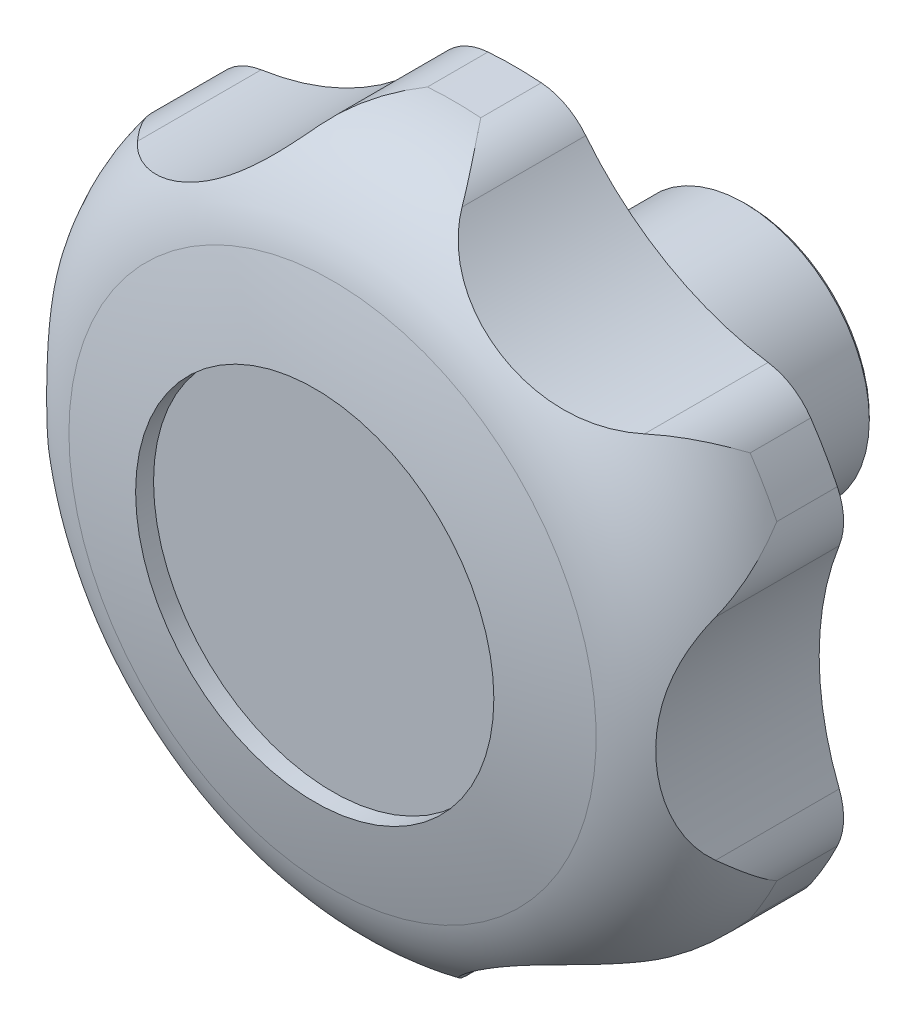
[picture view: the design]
ISO-10303-21;
HEADER;
FILE_DESCRIPTION(('STEP AP214'),'2;1');
FILE_NAME('part.step','',(''),(''),'','','');
FILE_SCHEMA(('AUTOMOTIVE_DESIGN { 1 0 10303 214 1 1 1 1 }'));
ENDSEC;
DATA;
#1=APPLICATION_CONTEXT('core data for automotive mechanical design processes');
#2=APPLICATION_PROTOCOL_DEFINITION('international standard','automotive_design',2000,#1);
#3=PRODUCT_CONTEXT('',#1,'mechanical');
#4=PRODUCT('Part','Part','',(#3));
#5=PRODUCT_RELATED_PRODUCT_CATEGORY('part','',(#4));
#6=PRODUCT_DEFINITION_FORMATION('','',#4);
#7=PRODUCT_DEFINITION_CONTEXT('part definition',#1,'design');
#8=PRODUCT_DEFINITION('design','',#6,#7);
#9=PRODUCT_DEFINITION_SHAPE('','',#8);
#10=(LENGTH_UNIT() NAMED_UNIT(*) SI_UNIT(.MILLI.,.METRE.));
#11=(NAMED_UNIT(*) PLANE_ANGLE_UNIT() SI_UNIT($,.RADIAN.));
#12=(NAMED_UNIT(*) SI_UNIT($,.STERADIAN.) SOLID_ANGLE_UNIT());
#13=UNCERTAINTY_MEASURE_WITH_UNIT(LENGTH_MEASURE(1.E-05),#10,'distance_accuracy_value','');
#14=(GEOMETRIC_REPRESENTATION_CONTEXT(3) GLOBAL_UNCERTAINTY_ASSIGNED_CONTEXT((#13)) GLOBAL_UNIT_ASSIGNED_CONTEXT((#10,
#11,#12)) REPRESENTATION_CONTEXT('',''));
#15=CARTESIAN_POINT('',(0.,0.,0.));
#16=DIRECTION('',(0.,0.,1.));
#17=DIRECTION('',(1.,0.,0.));
#18=AXIS2_PLACEMENT_3D('',#15,#16,#17);
#19=CARTESIAN_POINT('',(0.,0.,35.0080113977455));
#20=DIRECTION('',(0.,0.,1.));
#21=DIRECTION('',(-1.,0.,0.));
#22=AXIS2_PLACEMENT_3D('',#19,#20,#21);
#23=CYLINDRICAL_SURFACE('',#22,20.);
#24=CARTESIAN_POINT('',(0.,0.,13.));
#25=DIRECTION('',(0.,0.,1.));
#26=DIRECTION('',(-1.,0.,0.));
#27=AXIS2_PLACEMENT_3D('',#24,#25,#26);
#28=CIRCLE('',#27,20.);
#29=CARTESIAN_POINT('',(1.4880574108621,19.9445653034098,12.9999999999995));
#30=VERTEX_POINT('',#29);
#31=CARTESIAN_POINT('',(-1.48805741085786,19.94456530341,12.9999999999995));
#32=VERTEX_POINT('',#31);
#33=EDGE_CURVE('E459',#30,#32,#28,.T.);
#34=ORIENTED_EDGE('',*,*,#33,.T.);
#35=DIRECTION('',(0.,0.,1.));
#36=VECTOR('',#35,1.);
#37=CARTESIAN_POINT('',(-1.48805741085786,19.94456530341,-4.9960036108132E-13));
#38=LINE('',#37,#36);
#39=CARTESIAN_POINT('',(-1.48805741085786,19.94456530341,16.38093031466));
#40=VERTEX_POINT('',#39);
#41=EDGE_CURVE('E182',#32,#40,#38,.T.);
#42=ORIENTED_EDGE('',*,*,#41,.T.);
#43=CARTESIAN_POINT('',(0.,0.,16.38093031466));
#44=DIRECTION('',(0.,0.,1.));
#45=DIRECTION('',(-1.,0.,0.));
#46=AXIS2_PLACEMENT_3D('',#43,#44,#45);
#47=CIRCLE('',#46,20.);
#48=CARTESIAN_POINT('',(1.4880574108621,19.9445653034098,16.38093031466));
#49=VERTEX_POINT('',#48);
#50=EDGE_CURVE('E198',#49,#40,#47,.T.);
#51=ORIENTED_EDGE('',*,*,#50,.F.);
#52=DIRECTION('',(0.,0.,1.));
#53=VECTOR('',#52,1.);
#54=CARTESIAN_POINT('',(1.4880574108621,19.9445653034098,-4.9960036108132E-13));
#55=LINE('',#54,#53);
#56=EDGE_CURVE('E578',#30,#49,#55,.T.);
#57=ORIENTED_EDGE('',*,*,#56,.F.);
#58=EDGE_LOOP('',(#34,#42,#51,#57));
#59=FACE_BOUND('',#58,.T.);
#60=ADVANCED_FACE('F14',(#59),#23,.T.);
#61=CARTESIAN_POINT('',(18.0165289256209,8.68358713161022,12.9999999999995));
#62=VERTEX_POINT('',#61);
#63=CARTESIAN_POINT('',(16.5284715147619,11.2609781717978,13.));
#64=VERTEX_POINT('',#63);
#65=EDGE_CURVE('E463',#62,#64,#28,.T.);
#66=ORIENTED_EDGE('',*,*,#65,.T.);
#67=DIRECTION('',(0.,0.,1.));
#68=VECTOR('',#67,1.);
#69=CARTESIAN_POINT('',(16.5284715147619,11.2609781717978,-4.9960036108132E-13));
#70=LINE('',#69,#68);
#71=CARTESIAN_POINT('',(16.5284715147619,11.2609781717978,16.38093031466));
#72=VERTEX_POINT('',#71);
#73=EDGE_CURVE('E491',#64,#72,#70,.T.);
#74=ORIENTED_EDGE('',*,*,#73,.T.);
#75=CARTESIAN_POINT('',(18.0165289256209,8.68358713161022,16.38093031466));
#76=VERTEX_POINT('',#75);
#77=EDGE_CURVE('E553',#76,#72,#47,.T.);
#78=ORIENTED_EDGE('',*,*,#77,.F.);
#79=DIRECTION('',(0.,0.,1.));
#80=VECTOR('',#79,1.);
#81=CARTESIAN_POINT('',(18.0165289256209,8.68358713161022,-4.9960036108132E-13));
#82=LINE('',#81,#80);
#83=EDGE_CURVE('E493',#62,#76,#82,.T.);
#84=ORIENTED_EDGE('',*,*,#83,.F.);
#85=EDGE_LOOP('',(#66,#74,#78,#84));
#86=FACE_BOUND('',#85,.T.);
#87=ADVANCED_FACE('F429',(#86),#23,.T.);
#88=CARTESIAN_POINT('',(16.5284715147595,-11.260978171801,12.9999999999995));
#89=VERTEX_POINT('',#88);
#90=CARTESIAN_POINT('',(18.0165289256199,-8.68358713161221,13.));
#91=VERTEX_POINT('',#90);
#92=EDGE_CURVE('E476',#89,#91,#28,.T.);
#93=ORIENTED_EDGE('',*,*,#92,.T.);
#94=DIRECTION('',(0.,0.,1.));
#95=VECTOR('',#94,1.);
#96=CARTESIAN_POINT('',(18.0165289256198,-8.68358713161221,-4.9960036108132E-13));
#97=LINE('',#96,#95);
#98=CARTESIAN_POINT('',(18.0165289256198,-8.68358713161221,16.38093031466));
#99=VERTEX_POINT('',#98);
#100=EDGE_CURVE('E569',#91,#99,#97,.T.);
#101=ORIENTED_EDGE('',*,*,#100,.T.);
#102=CARTESIAN_POINT('',(16.5284715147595,-11.260978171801,16.38093031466));
#103=VERTEX_POINT('',#102);
#104=EDGE_CURVE('E548',#103,#99,#47,.T.);
#105=ORIENTED_EDGE('',*,*,#104,.F.);
#106=DIRECTION('',(0.,0.,1.));
#107=VECTOR('',#106,1.);
#108=CARTESIAN_POINT('',(16.5284715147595,-11.260978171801,-4.9960036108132E-13));
#109=LINE('',#108,#107);
#110=EDGE_CURVE('E612',#89,#103,#109,.T.);
#111=ORIENTED_EDGE('',*,*,#110,.F.);
#112=EDGE_LOOP('',(#93,#101,#105,#111));
#113=FACE_BOUND('',#112,.T.);
#114=ADVANCED_FACE('F437',(#113),#23,.T.);
#115=CARTESIAN_POINT('',(-1.48805741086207,-19.94456530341,12.9999999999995));
#116=VERTEX_POINT('',#115);
#117=CARTESIAN_POINT('',(1.48805741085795,-19.94456530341,13.));
#118=VERTEX_POINT('',#117);
#119=EDGE_CURVE('E470',#116,#118,#28,.T.);
#120=ORIENTED_EDGE('',*,*,#119,.T.);
#121=DIRECTION('',(0.,0.,1.));
#122=VECTOR('',#121,1.);
#123=CARTESIAN_POINT('',(1.48805741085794,-19.94456530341,-4.9960036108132E-13));
#124=LINE('',#123,#122);
#125=CARTESIAN_POINT('',(1.48805741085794,-19.94456530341,16.38093031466));
#126=VERTEX_POINT('',#125);
#127=EDGE_CURVE('E604',#118,#126,#124,.T.);
#128=ORIENTED_EDGE('',*,*,#127,.T.);
#129=CARTESIAN_POINT('',(-1.48805741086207,-19.94456530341,16.38093031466));
#130=VERTEX_POINT('',#129);
#131=EDGE_CURVE('E543',#130,#126,#47,.T.);
#132=ORIENTED_EDGE('',*,*,#131,.F.);
#133=DIRECTION('',(0.,0.,1.));
#134=VECTOR('',#133,1.);
#135=CARTESIAN_POINT('',(-1.48805741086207,-19.94456530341,-4.9960036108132E-13));
#136=LINE('',#135,#134);
#137=EDGE_CURVE('E602',#116,#130,#136,.T.);
#138=ORIENTED_EDGE('',*,*,#137,.F.);
#139=EDGE_LOOP('',(#120,#128,#132,#138));
#140=FACE_BOUND('',#139,.T.);
#141=ADVANCED_FACE('F449',(#140),#23,.T.);
#142=CARTESIAN_POINT('',(-18.0165289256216,-8.68358713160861,12.9999999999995));
#143=VERTEX_POINT('',#142);
#144=CARTESIAN_POINT('',(-16.528471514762,-11.2609781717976,13.));
#145=VERTEX_POINT('',#144);
#146=EDGE_CURVE('E462',#143,#145,#28,.T.);
#147=ORIENTED_EDGE('',*,*,#146,.T.);
#148=DIRECTION('',(0.,0.,1.));
#149=VECTOR('',#148,1.);
#150=CARTESIAN_POINT('',(-16.5284715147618,-11.2609781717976,-4.9960036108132E-13));
#151=LINE('',#150,#149);
#152=CARTESIAN_POINT('',(-16.5284715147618,-11.2609781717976,16.38093031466));
#153=VERTEX_POINT('',#152);
#154=EDGE_CURVE('E594',#145,#153,#151,.T.);
#155=ORIENTED_EDGE('',*,*,#154,.T.);
#156=CARTESIAN_POINT('',(-18.0165289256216,-8.68358713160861,16.38093031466));
#157=VERTEX_POINT('',#156);
#158=EDGE_CURVE('E474',#157,#153,#47,.T.);
#159=ORIENTED_EDGE('',*,*,#158,.F.);
#160=DIRECTION('',(0.,0.,1.));
#161=VECTOR('',#160,1.);
#162=CARTESIAN_POINT('',(-18.0165289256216,-8.68358713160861,-4.9960036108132E-13));
#163=LINE('',#162,#161);
#164=EDGE_CURVE('E592',#143,#157,#163,.T.);
#165=ORIENTED_EDGE('',*,*,#164,.F.);
#166=EDGE_LOOP('',(#147,#155,#159,#165));
#167=FACE_BOUND('',#166,.T.);
#168=ADVANCED_FACE('F441',(#167),#23,.T.);
#169=CARTESIAN_POINT('',(-16.5284715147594,11.260978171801,12.9999999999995));
#170=VERTEX_POINT('',#169);
#171=CARTESIAN_POINT('',(-18.0165289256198,8.68358713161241,13.));
#172=VERTEX_POINT('',#171);
#173=EDGE_CURVE('E454',#170,#172,#28,.T.);
#174=ORIENTED_EDGE('',*,*,#173,.T.);
#175=DIRECTION('',(0.,0.,1.));
#176=VECTOR('',#175,1.);
#177=CARTESIAN_POINT('',(-18.0165289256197,8.68358713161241,-4.9960036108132E-13));
#178=LINE('',#177,#176);
#179=CARTESIAN_POINT('',(-18.0165289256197,8.68358713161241,16.38093031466));
#180=VERTEX_POINT('',#179);
#181=EDGE_CURVE('E37',#172,#180,#178,.T.);
#182=ORIENTED_EDGE('',*,*,#181,.T.);
#183=CARTESIAN_POINT('',(-16.5284715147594,11.260978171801,16.38093031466));
#184=VERTEX_POINT('',#183);
#185=EDGE_CURVE('E469',#184,#180,#47,.T.);
#186=ORIENTED_EDGE('',*,*,#185,.F.);
#187=DIRECTION('',(0.,0.,1.));
#188=VECTOR('',#187,1.);
#189=CARTESIAN_POINT('',(-16.5284715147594,11.260978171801,-4.9960036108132E-13));
#190=LINE('',#189,#188);
#191=EDGE_CURVE('E457',#170,#184,#190,.T.);
#192=ORIENTED_EDGE('',*,*,#191,.F.);
#193=EDGE_LOOP('',(#174,#182,#186,#192));
#194=FACE_BOUND('',#193,.T.);
#195=ADVANCED_FACE('F431',(#194),#23,.T.);
#196=CARTESIAN_POINT('',(0.,0.,-35.0000000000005));
#197=DIRECTION('',(-1.,0.,0.));
#198=DIRECTION('',(0.,0.,-1.));
#199=AXIS2_PLACEMENT_3D('',#196,#197,#198);
#200=SPHERICAL_SURFACE('',#199,60.);
#201=CARTESIAN_POINT('',(0.,0.,-35.0000000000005));
#202=DIRECTION('',(0.,0.,1.));
#203=DIRECTION('',(-1.,0.,0.));
#204=AXIS2_PLACEMENT_3D('',#201,#202,#203);
#205=SPHERICAL_SURFACE('',#204,60.);
#206=CARTESIAN_POINT('',(0.,0.,23.167090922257));
#207=DIRECTION('',(0.,0.,1.));
#208=DIRECTION('',(-1.,0.,0.));
#209=AXIS2_PLACEMENT_3D('',#206,#207,#208);
#210=CIRCLE('',#209,14.7169811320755);
#211=CARTESIAN_POINT('',(-14.7169811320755,0.,23.167090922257));
#212=VERTEX_POINT('',#211);
#213=EDGE_CURVE('E540',#212,#212,#210,.T.);
#214=ORIENTED_EDGE('',*,*,#213,.T.);
#215=EDGE_LOOP('',(#214));
#216=FACE_BOUND('',#215,.T.);
#217=CARTESIAN_POINT('',(0.,0.,24.160797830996));
#218=DIRECTION('',(0.,0.,1.));
#219=DIRECTION('',(-1.,0.,0.));
#220=AXIS2_PLACEMENT_3D('',#217,#218,#219);
#221=CIRCLE('',#220,10.);
#222=CARTESIAN_POINT('',(-10.,0.,24.160797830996));
#223=VERTEX_POINT('',#222);
#224=EDGE_CURVE('E199',#223,#223,#221,.T.);
#225=ORIENTED_EDGE('',*,*,#224,.F.);
#226=EDGE_LOOP('',(#225));
#227=FACE_BOUND('',#226,.T.);
#228=ADVANCED_FACE('F16',(#216,#227),#205,.T.);
#229=CARTESIAN_POINT('',(0.,0.,16.38093031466));
#230=DIRECTION('',(0.,0.,1.));
#231=DIRECTION('',(-1.,0.,0.));
#232=AXIS2_PLACEMENT_3D('',#229,#230,#231);
#233=TOROIDAL_SURFACE('',#232,13.,7.);
#234=CARTESIAN_POINT('',(1.48805741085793,19.94456530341,16.38093031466));
#235=CARTESIAN_POINT('',(1.49147422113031,19.9443103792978,16.3853314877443));
#236=CARTESIAN_POINT('',(1.49489072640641,19.9440504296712,16.389732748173));
#237=CARTESIAN_POINT('',(1.81379375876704,19.9193149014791,16.8006005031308));
#238=CARTESIAN_POINT('',(2.12658065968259,19.8519874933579,17.2077752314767));
#239=CARTESIAN_POINT('',(2.72890668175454,19.6321878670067,18.0173039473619));
#240=CARTESIAN_POINT('',(3.01841511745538,19.4796053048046,18.4196509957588));
#241=CARTESIAN_POINT('',(3.4111136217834,19.1940432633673,19.0006622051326));
#242=CARTESIAN_POINT('',(3.53138560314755,19.0939385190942,19.1842811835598));
#243=CARTESIAN_POINT('',(3.759784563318,18.875652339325,19.5475677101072));
#244=CARTESIAN_POINT('',(3.86793749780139,18.7575108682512,19.7272430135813));
#245=CARTESIAN_POINT('',(3.96899762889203,18.6302715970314,19.9047576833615));
#246=B_SPLINE_CURVE_WITH_KNOTS('',3,(#234,#235,#236,#237,#238,#239,#240,#241,#242,#243,#244,
#245),.UNSPECIFIED.,.F.,.F.,(4,2,2,2,2,4),(0.,0.0167332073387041,1.56205380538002,
3.1093791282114,3.83223807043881,4.55351799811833),.UNSPECIFIED.);
#247=CARTESIAN_POINT('',(3.96883886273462,18.6304715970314,19.9044786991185));
#248=VERTEX_POINT('',#247);
#249=EDGE_CURVE('E200',#49,#248,#246,.T.);
#250=ORIENTED_EDGE('',*,*,#249,.F.);
#251=ORIENTED_EDGE('',*,*,#50,.T.);
#252=CARTESIAN_POINT('',(-3.96899762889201,18.6302715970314,19.9047576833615));
#253=CARTESIAN_POINT('',(-3.87488306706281,18.7487894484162,19.7394301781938));
#254=CARTESIAN_POINT('',(-3.77455997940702,18.8594451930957,19.5721519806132));
#255=CARTESIAN_POINT('',(-3.56354943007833,19.0648747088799,19.234567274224));
#256=CARTESIAN_POINT('',(-3.45286825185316,19.1596580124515,19.0642626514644));
#257=CARTESIAN_POINT('',(-3.22337066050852,19.3331052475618,18.7217368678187));
#258=CARTESIAN_POINT('',(-3.10457584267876,19.4118099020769,18.5495217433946));
#259=CARTESIAN_POINT('',(-2.86030415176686,19.5533565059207,18.2033602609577));
#260=CARTESIAN_POINT('',(-2.73482744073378,19.6161988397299,18.0294139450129));
#261=CARTESIAN_POINT('',(-2.42924956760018,19.7472078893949,17.6128190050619));
#262=CARTESIAN_POINT('',(-2.24677265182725,19.8080525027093,17.3695899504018));
#263=CARTESIAN_POINT('',(-1.87597960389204,19.8989790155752,16.8822329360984));
#264=CARTESIAN_POINT('',(-1.68767071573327,19.9290976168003,16.638106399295));
#265=CARTESIAN_POINT('',(-1.49489075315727,19.9440504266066,16.3897327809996));
#266=CARTESIAN_POINT('',(-1.49147424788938,19.9443103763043,16.385331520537));
#267=CARTESIAN_POINT('',(-1.4880574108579,19.94456530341,16.38093031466));
#268=B_SPLINE_CURVE_WITH_KNOTS('',3,(#252,#253,#254,#255,#256,#257,#258,#259,#260,#261,#262,
#263,#264,#265,#266,#267),.UNSPECIFIED.,.F.,.F.,(4,2,2,2,2,2,2,4),(0.,0.672016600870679,
1.34362815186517,2.01351700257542,2.68338961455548,3.61205098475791,4.53960178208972,
4.55633498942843),.UNSPECIFIED.);
#269=CARTESIAN_POINT('',(-3.96883886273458,18.6304715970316,19.9044786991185));
#270=VERTEX_POINT('',#269);
#271=EDGE_CURVE('E186',#270,#40,#268,.T.);
#272=ORIENTED_EDGE('',*,*,#271,.F.);
#273=CARTESIAN_POINT('',(-3.96868008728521,18.6306715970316,19.9041996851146));
#274=CARTESIAN_POINT('',(-4.04437009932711,18.5352984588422,20.0373324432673));
#275=CARTESIAN_POINT('',(-4.12526413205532,18.4356613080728,20.1643450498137));
#276=CARTESIAN_POINT('',(-4.29682494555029,18.2299121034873,20.4055808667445));
#277=CARTESIAN_POINT('',(-4.38747947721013,18.1238082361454,20.5198197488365));
#278=CARTESIAN_POINT('',(-4.57713747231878,17.9080462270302,20.734184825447));
#279=CARTESIAN_POINT('',(-4.67604562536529,17.7984357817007,20.8344439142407));
#280=CARTESIAN_POINT('',(-4.88238077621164,17.5763891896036,21.0223145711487));
#281=CARTESIAN_POINT('',(-4.98981004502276,17.4639522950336,21.1099227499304));
#282=CARTESIAN_POINT('',(-5.21195811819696,17.2384215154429,21.2724206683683));
#283=CARTESIAN_POINT('',(-5.32664134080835,17.1253329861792,21.3473667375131));
#284=CARTESIAN_POINT('',(-5.5630216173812,16.8994018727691,21.4855727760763));
#285=CARTESIAN_POINT('',(-5.68471815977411,16.7865592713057,21.5488335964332));
#286=CARTESIAN_POINT('',(-5.93480326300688,16.5619776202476,21.6645190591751));
#287=CARTESIAN_POINT('',(-6.06320974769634,16.4502425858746,21.7169126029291));
#288=CARTESIAN_POINT('',(-6.32576627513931,16.2291643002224,21.8113760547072));
#289=CARTESIAN_POINT('',(-6.45991755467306,16.1198215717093,21.8534437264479));
#290=CARTESIAN_POINT('',(-6.79339160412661,15.8570291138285,21.9443164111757));
#291=CARTESIAN_POINT('',(-6.99547686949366,15.7052831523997,21.9879752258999));
#292=CARTESIAN_POINT('',(-7.40871955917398,15.410195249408,22.0571569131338));
#293=CARTESIAN_POINT('',(-7.61988028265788,15.2668564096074,22.0826731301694));
#294=CARTESIAN_POINT('',(-8.05020035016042,14.9896326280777,22.1167506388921));
#295=CARTESIAN_POINT('',(-8.26937403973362,14.8557660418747,22.1252798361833));
#296=CARTESIAN_POINT('',(-8.71390124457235,14.59876043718,22.1256982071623));
#297=CARTESIAN_POINT('',(-8.93925403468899,14.4756201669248,22.1175893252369));
#298=CARTESIAN_POINT('',(-9.3969107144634,14.2396244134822,22.0841784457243));
#299=CARTESIAN_POINT('',(-9.62926146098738,14.1268834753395,22.0587061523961));
#300=CARTESIAN_POINT('',(-10.0969036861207,13.9136966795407,21.9891901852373));
#301=CARTESIAN_POINT('',(-10.3321956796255,13.8132530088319,21.9451432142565));
#302=CARTESIAN_POINT('',(-10.8026152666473,13.6254517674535,21.8367845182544));
#303=CARTESIAN_POINT('',(-11.0377415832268,13.5380595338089,21.7725279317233));
#304=CARTESIAN_POINT('',(-11.5052304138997,13.37642671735,21.6215210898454));
#305=CARTESIAN_POINT('',(-11.7375946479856,13.3021775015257,21.5347856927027));
#306=CARTESIAN_POINT('',(-12.1176745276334,13.1898767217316,21.3703811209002));
#307=CARTESIAN_POINT('',(-12.2673166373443,13.1480997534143,21.2996511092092));
#308=CARTESIAN_POINT('',(-12.5622706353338,13.0702110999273,21.1469698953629));
#309=CARTESIAN_POINT('',(-12.707583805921,13.0340977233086,21.0650220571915));
#310=CARTESIAN_POINT('',(-12.9920623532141,12.967442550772,20.8897703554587));
#311=CARTESIAN_POINT('',(-13.1312411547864,12.9368880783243,20.7964931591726));
#312=CARTESIAN_POINT('',(-13.4021505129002,12.880989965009,20.5983767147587));
#313=CARTESIAN_POINT('',(-13.5338850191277,12.8556435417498,20.4935436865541));
#314=CARTESIAN_POINT('',(-13.7470664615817,12.817207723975,20.3083350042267));
#315=CARTESIAN_POINT('',(-13.8309740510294,12.8028082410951,20.2310445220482));
#316=CARTESIAN_POINT('',(-13.9941817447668,12.7760624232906,20.0714083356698));
#317=CARTESIAN_POINT('',(-14.0734817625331,12.7637161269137,19.9890625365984));
#318=CARTESIAN_POINT('',(-14.1502422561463,12.7523213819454,19.9042577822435));
#319=B_SPLINE_CURVE_WITH_KNOTS('',3,(#273,#274,#275,#276,#277,#278,#279,#280,#281,#282,#283,
#284,#285,#286,#287,#288,#289,#290,#291,#292,#293,#294,#295,#296,#297,#298,#299,#300,#301,#302,
#303,#304,#305,#306,#307,#308,#309,#310,#311,#312,#313,#314,#315,#316,#317,#318),.UNSPECIFIED.,
.F.,.F.,(4,2,2,2,2,2,2,2,2,2,2,2,2,2,2,2,2,2,2,2,2,2,4),(0.,0.540904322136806,1.08113756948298,
1.61582234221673,2.15065009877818,2.68303208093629,3.21537527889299,3.7492214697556,
4.28318317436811,5.05149336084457,5.82008525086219,6.5901279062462,7.36008057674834,
8.13769549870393,8.91544851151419,9.69109770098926,10.4662354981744,10.9779030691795,
11.4894175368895,11.9997505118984,12.5098101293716,12.8545587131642,13.1993137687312),.UNSPECIFIED.);
#320=CARTESIAN_POINT('',(-14.1500422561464,12.7523510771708,19.9044786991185));
#321=VERTEX_POINT('',#320);
#322=EDGE_CURVE('E174',#270,#321,#319,.T.);
#323=ORIENTED_EDGE('',*,*,#322,.T.);
#324=CARTESIAN_POINT('',(-16.5284715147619,11.2609781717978,16.38093031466));
#325=CARTESIAN_POINT('',(-16.526542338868,11.2638097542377,16.3853314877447));
#326=CARTESIAN_POINT('',(-16.5246089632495,11.2666385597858,16.3897327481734));
#327=CARTESIAN_POINT('',(-16.3437358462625,11.5304489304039,16.8006005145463));
#328=CARTESIAN_POINT('',(-16.1290351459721,11.7676666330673,17.2077752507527));
#329=CARTESIAN_POINT('',(-15.6375200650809,12.1793964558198,18.0173039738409));
#330=CARTESIAN_POINT('',(-15.3606254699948,12.3538268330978,18.4196510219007));
#331=CARTESIAN_POINT('',(-14.9169799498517,12.5511292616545,19.0006521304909));
#332=CARTESIAN_POINT('',(-14.7701590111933,12.6052330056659,19.1842611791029));
#333=CARTESIAN_POINT('',(-14.4669357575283,12.6938865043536,19.5475282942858));
#334=CARTESIAN_POINT('',(-14.3105550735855,12.7284787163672,19.72719411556));
#335=CARTESIAN_POINT('',(-14.1498422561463,12.7523807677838,19.9046996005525));
#336=B_SPLINE_CURVE_WITH_KNOTS('',3,(#324,#325,#326,#327,#328,#329,#330,#331,#332,#333,#334,
#335),.UNSPECIFIED.,.F.,.F.,(4,2,2,2,2,4),(0.,0.0167332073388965,1.56205384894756,
3.10937912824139,3.83219873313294,4.5534393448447),.UNSPECIFIED.);
#337=EDGE_CURVE('E181',#184,#321,#336,.T.);
#338=ORIENTED_EDGE('',*,*,#337,.F.);
#339=ORIENTED_EDGE('',*,*,#185,.T.);
#340=CARTESIAN_POINT('',(-18.1188021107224,5.8779205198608,19.904713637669));
#341=CARTESIAN_POINT('',(-18.1743828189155,6.01868604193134,19.7393849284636));
#342=CARTESIAN_POINT('',(-18.2200504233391,6.16089717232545,19.5721055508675));
#343=CARTESIAN_POINT('',(-18.2924491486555,6.44635409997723,19.2345185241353));
#344=CARTESIAN_POINT('',(-18.3191916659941,6.58959922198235,19.0642127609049));
#345=CARTESIAN_POINT('',(-18.354649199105,6.87507491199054,18.7216847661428));
#346=CARTESIAN_POINT('',(-18.3634102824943,7.01730713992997,18.5494685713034));
#347=CARTESIAN_POINT('',(-18.3638538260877,7.2996268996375,18.2033049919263));
#348=CARTESIAN_POINT('',(-18.3555367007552,7.43971448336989,18.029357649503));
#349=CARTESIAN_POINT('',(-18.3162014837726,7.76984941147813,17.6127710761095));
#350=CARTESIAN_POINT('',(-18.2776557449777,7.95829337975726,17.3695515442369));
#351=CARTESIAN_POINT('',(-18.1710057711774,8.32485756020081,16.8822136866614));
#352=CARTESIAN_POINT('',(-18.1029369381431,8.50298984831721,16.638096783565));
#353=CARTESIAN_POINT('',(-18.0194997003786,8.67741184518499,16.3897327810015));
#354=CARTESIAN_POINT('',(-18.0180165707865,8.68050060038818,16.3853315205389));
#355=CARTESIAN_POINT('',(-18.0165289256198,8.68358713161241,16.38093031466));
#356=B_SPLINE_CURVE_WITH_KNOTS('',3,(#340,#341,#342,#343,#344,#345,#346,#347,#348,#349,#350,
#351,#352,#353,#354,#355),.UNSPECIFIED.,.F.,.F.,(4,2,2,2,2,2,2,4),(0.,0.672020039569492,
1.34363505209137,2.01352725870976,2.68340320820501,3.61202792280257,4.539542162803,
4.55627537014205),.UNSPECIFIED.);
#357=CARTESIAN_POINT('',(-18.118881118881,5.87812051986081,19.9044786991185));
#358=VERTEX_POINT('',#357);
#359=EDGE_CURVE('E248',#358,#180,#356,.T.);
#360=ORIENTED_EDGE('',*,*,#359,.F.);
#361=CARTESIAN_POINT('',(-18.1189601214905,5.87832051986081,19.9042437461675));
#362=CARTESIAN_POINT('',(-18.0742090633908,5.76508237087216,20.0373759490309));
#363=CARTESIAN_POINT('',(-18.0283673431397,5.64520539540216,20.1643878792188));
#364=CARTESIAN_POINT('',(-17.9359630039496,5.39375057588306,20.4056221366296));
#365=CARTESIAN_POINT('',(-17.8894013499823,5.2621874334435,20.5198601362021));
#366=CARTESIAN_POINT('',(-17.7973745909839,4.99005371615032,20.7342232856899));
#367=CARTESIAN_POINT('',(-17.7519031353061,4.84958953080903,20.8344813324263));
#368=CARTESIAN_POINT('',(-17.6627726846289,4.55987085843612,21.0223497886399));
#369=CARTESIAN_POINT('',(-17.619114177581,4.41061403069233,21.1099568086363));
#370=CARTESIAN_POINT('',(-17.5348731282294,4.10545908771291,21.2724523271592));
#371=CARTESIAN_POINT('',(-17.4942774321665,3.94959446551,21.3473971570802));
#372=CARTESIAN_POINT('',(-17.4168061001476,3.63191414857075,21.4856006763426));
#373=CARTESIAN_POINT('',(-17.3799301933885,3.47009888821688,21.54886021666));
#374=CARTESIAN_POINT('',(-17.3104802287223,3.14122478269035,21.6645431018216));
#375=CARTESIAN_POINT('',(-17.2779186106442,2.97415242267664,21.7169353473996));
#376=CARTESIAN_POINT('',(-17.2177386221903,2.63622963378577,21.8113961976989));
#377=CARTESIAN_POINT('',(-17.1901213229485,2.46537839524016,21.8534625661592));
#378=CARTESIAN_POINT('',(-17.1292751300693,2.0451819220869,21.9443320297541));
#379=CARTESIAN_POINT('',(-17.098903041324,1.79429623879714,21.9879889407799));
#380=CARTESIAN_POINT('',(-17.0499732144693,1.2888703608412,22.0571668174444));
#381=CARTESIAN_POINT('',(-17.0314198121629,1.03432885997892,22.0826811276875));
#382=CARTESIAN_POINT('',(-17.0064997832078,0.523045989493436,22.1167547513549));
#383=CARTESIAN_POINT('',(-17.0001562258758,0.266301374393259,22.1252819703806));
#384=CARTESIAN_POINT('',(-16.9998494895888,-0.247175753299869,22.125696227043));
#385=CARTESIAN_POINT('',(-17.0058848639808,-0.503908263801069,22.1175852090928));
#386=CARTESIAN_POINT('',(-17.0303381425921,-1.01825026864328,22.0841697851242));
#387=CARTESIAN_POINT('',(-17.0488786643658,-1.27584306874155,22.0586950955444));
#388=CARTESIAN_POINT('',(-17.098077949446,-1.78742757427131,21.9891739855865));
#389=CARTESIAN_POINT('',(-17.128738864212,-2.04141863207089,21.9451242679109));
#390=CARTESIAN_POINT('',(-17.2013113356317,-2.54271489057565,21.8367596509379));
#391=CARTESIAN_POINT('',(-17.2431922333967,-2.79003631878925,21.7724998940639));
#392=CARTESIAN_POINT('',(-17.3369616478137,-3.27570930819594,21.6214862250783));
#393=CARTESIAN_POINT('',(-17.3888435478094,-3.51406667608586,21.5347471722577));
#394=CARTESIAN_POINT('',(-17.4816300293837,-3.89937284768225,21.3703368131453));
#395=CARTESIAN_POINT('',(-17.5202715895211,-4.04985295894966,21.2996049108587));
#396=CARTESIAN_POINT('',(-17.6002956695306,-4.34423029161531,21.1469199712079));
#397=CARTESIAN_POINT('',(-17.6416773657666,-4.48812946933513,21.0649702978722));
#398=CARTESIAN_POINT('',(-17.7261917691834,-4.76781773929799,20.8897150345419));
#399=CARTESIAN_POINT('',(-17.769320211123,-4.90362479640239,20.7964361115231));
#400=CARTESIAN_POINT('',(-17.8563654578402,-5.16618299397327,20.5983163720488));
#401=CARTESIAN_POINT('',(-17.9002818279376,-5.29293894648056,20.4934817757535));
#402=CARTESIAN_POINT('',(-17.9735824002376,-5.49676399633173,20.3082786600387));
#403=CARTESIAN_POINT('',(-18.0030624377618,-5.57661965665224,20.2309958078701));
#404=CARTESIAN_POINT('',(-18.0614968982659,-5.73131526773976,20.0713760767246));
#405=CARTESIAN_POINT('',(-18.0904513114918,-5.80615512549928,19.9890391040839));
#406=CARTESIAN_POINT('',(-18.1189601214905,-5.87832051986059,19.9042437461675));
#407=B_SPLINE_CURVE_WITH_KNOTS('',3,(#361,#362,#363,#364,#365,#366,#367,#368,#369,#370,#371,
#372,#373,#374,#375,#376,#377,#378,#379,#380,#381,#382,#383,#384,#385,#386,#387,#388,#389,#390,
#391,#392,#393,#394,#395,#396,#397,#398,#399,#400,#401,#402,#403,#404,#405,#406),.UNSPECIFIED.,
.F.,.F.,(4,2,2,2,2,2,2,2,2,2,2,2,2,2,2,2,2,2,2,2,2,2,4),(0.,0.54090742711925,1.08114375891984,
1.61583154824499,2.15066232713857,2.68304725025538,3.21539338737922,3.74924255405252,
4.28320723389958,5.05152112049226,5.82011670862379,6.59016306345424,7.36011943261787,
8.13773742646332,8.91549351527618,9.6911456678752,10.466286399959,10.9779506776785,
11.489461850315,11.9997915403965,12.5098478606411,12.8545572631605,13.1992730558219),.UNSPECIFIED.);
#408=CARTESIAN_POINT('',(-18.118881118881,-5.87812051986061,19.9044786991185));
#409=VERTEX_POINT('',#408);
#410=EDGE_CURVE('E254',#358,#409,#407,.T.);
#411=ORIENTED_EDGE('',*,*,#410,.T.);
#412=CARTESIAN_POINT('',(-18.0165289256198,-8.68358713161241,16.38093031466));
#413=CARTESIAN_POINT('',(-18.0180165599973,-8.68050062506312,16.3853314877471));
#414=CARTESIAN_POINT('',(-18.0194996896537,-8.67741186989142,16.3897327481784));
#415=CARTESIAN_POINT('',(-18.1575296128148,-8.38886597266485,16.8006005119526));
#416=CARTESIAN_POINT('',(-18.2556158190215,-8.0843208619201,17.2077752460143));
#417=CARTESIAN_POINT('',(-18.3664267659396,-7.45279140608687,18.0173039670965));
#418=CARTESIAN_POINT('',(-18.3790406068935,-7.12577846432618,18.419651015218));
#419=CARTESIAN_POINT('',(-18.3280865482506,-6.6429169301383,19.0006545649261));
#420=CARTESIAN_POINT('',(-18.3015308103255,-6.48871235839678,19.1842660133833));
#421=CARTESIAN_POINT('',(-18.2266938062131,-6.18178255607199,19.5475378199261));
#422=CARTESIAN_POINT('',(-18.1784601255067,-6.02905482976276,19.7272059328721));
#423=CARTESIAN_POINT('',(-18.1188021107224,-5.87792051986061,19.904713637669));
#424=B_SPLINE_CURVE_WITH_KNOTS('',3,(#412,#413,#414,#415,#416,#417,#418,#419,#420,#421,#422,
#423),.UNSPECIFIED.,.F.,.F.,(4,2,2,2,2,4),(0.,0.0167332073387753,1.56205383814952,
3.10937912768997,3.83220823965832,4.55345835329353),.UNSPECIFIED.);
#425=EDGE_CURVE('E276',#157,#409,#424,.T.);
#426=ORIENTED_EDGE('',*,*,#425,.F.);
#427=ORIENTED_EDGE('',*,*,#158,.T.);
#428=CARTESIAN_POINT('',(-14.1498422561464,-12.7523807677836,19.9046996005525));
#429=CARTESIAN_POINT('',(-14.2995391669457,-12.7301317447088,19.7393705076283));
#430=CARTESIAN_POINT('',(-14.4455314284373,-12.6985749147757,19.5720907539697));
#431=CARTESIAN_POINT('',(-14.7289436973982,-12.6185444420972,19.2345029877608));
#432=CARTESIAN_POINT('',(-14.8663688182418,-12.5700810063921,19.0641968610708));
#433=CARTESIAN_POINT('',(-15.1313266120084,-12.4580491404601,18.7216681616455));
#434=CARTESIAN_POINT('',(-15.2588837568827,-12.3945197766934,18.549451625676));
#435=CARTESIAN_POINT('',(-15.5036013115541,-12.2537428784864,18.2032873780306));
#436=CARTESIAN_POINT('',(-15.6207619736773,-12.1764956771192,18.0293397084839));
#437=CARTESIAN_POINT('',(-15.8869968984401,-11.9773632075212,17.6127558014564));
#438=CARTESIAN_POINT('',(-16.0309190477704,-11.8497608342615,17.3695393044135));
#439=CARTESIAN_POINT('',(-16.2950440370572,-11.5741201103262,16.8822075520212));
#440=CARTESIAN_POINT('',(-16.4152750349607,-11.4261063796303,16.6380937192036));
#441=CARTESIAN_POINT('',(-16.524608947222,-11.2666385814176,16.3897327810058));
#442=CARTESIAN_POINT('',(-16.5265423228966,-11.2638097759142,16.3853315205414));
#443=CARTESIAN_POINT('',(-16.5284715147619,-11.2609781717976,16.38093031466));
#444=B_SPLINE_CURVE_WITH_KNOTS('',3,(#428,#429,#430,#431,#432,#433,#434,#435,#436,#437,#438,
#439,#440,#441,#442,#443),.UNSPECIFIED.,.F.,.F.,(4,2,2,2,2,2,2,4),(0.,0.67202113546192,
1.34363725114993,2.01353052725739,2.68340754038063,3.61202057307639,4.53952316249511,
4.55625636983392),.UNSPECIFIED.);
#445=CARTESIAN_POINT('',(-14.1500422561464,-12.752351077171,19.9044786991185));
#446=VERTEX_POINT('',#445);
#447=EDGE_CURVE('E282',#446,#153,#444,.T.);
#448=ORIENTED_EDGE('',*,*,#447,.F.);
#449=CARTESIAN_POINT('',(-14.1502422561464,-12.7523213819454,19.9042577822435));
#450=CARTESIAN_POINT('',(-14.0297989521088,-12.7701850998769,20.0373898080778));
#451=CARTESIAN_POINT('',(-13.903060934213,-12.790423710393,20.1644015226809));
#452=CARTESIAN_POINT('',(-13.6390912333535,-12.8361270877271,20.4056352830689));
#453=CARTESIAN_POINT('',(-13.5018727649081,-12.8615853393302,20.519873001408));
#454=CARTESIAN_POINT('',(-13.2201834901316,-12.917955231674,20.7342355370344));
#455=CARTESIAN_POINT('',(-13.075801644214,-12.9488081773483,20.8344932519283));
#456=CARTESIAN_POINT('',(-12.7803316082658,-13.0164788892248,21.0223610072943));
#457=CARTESIAN_POINT('',(-12.6292416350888,-13.0532982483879,21.1099676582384));
#458=CARTESIAN_POINT('',(-12.3228482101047,-13.1329214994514,21.2724624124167));
#459=CARTESIAN_POINT('',(-12.1675671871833,-13.1756972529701,21.3474068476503));
#460=CARTESIAN_POINT('',(-11.8537114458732,-13.2674459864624,21.4856095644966));
#461=CARTESIAN_POINT('',(-11.6951369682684,-13.3164185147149,21.5488686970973));
#462=CARTESIAN_POINT('',(-11.3755979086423,-13.420710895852,21.6645507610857));
#463=CARTESIAN_POINT('',(-11.2146278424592,-13.476048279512,21.7169425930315));
#464=CARTESIAN_POINT('',(-10.8918874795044,-13.5928930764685,21.8114026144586));
#465=CARTESIAN_POINT('',(-10.7301170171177,-13.6544018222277,21.8534685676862));
#466=CARTESIAN_POINT('',(-10.3357924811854,-13.8118067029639,21.9443370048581));
#467=CARTESIAN_POINT('',(-10.1033327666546,-13.9109471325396,21.9879933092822));
#468=CARTESIAN_POINT('',(-9.64115569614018,-14.1212867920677,22.05716997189));
#469=CARTESIAN_POINT('',(-9.41143937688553,-14.2324904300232,22.0826836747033));
#470=CARTESIAN_POINT('',(-8.95619505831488,-14.4665517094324,22.1167560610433));
#471=CARTESIAN_POINT('',(-8.73067578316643,-14.5894309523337,22.1252826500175));
#472=CARTESIAN_POINT('',(-8.28583797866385,-14.8459051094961,22.1256955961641));
#473=CARTESIAN_POINT('',(-8.06651872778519,-14.9794987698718,22.1175838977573));
#474=CARTESIAN_POINT('',(-7.63331213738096,-15.2578481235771,22.0841670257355));
#475=CARTESIAN_POINT('',(-7.41950056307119,-15.4027016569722,22.0586915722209));
#476=CARTESIAN_POINT('',(-7.00105526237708,-15.7011028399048,21.989168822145));
#477=CARTESIAN_POINT('',(-6.79642317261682,-15.8546520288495,21.94511822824));
#478=CARTESIAN_POINT('',(-6.39857455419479,-16.1681507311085,21.8367517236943));
#479=CARTESIAN_POINT('',(-6.20532864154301,-16.3280818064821,21.7724909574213));
#480=CARTESIAN_POINT('',(-5.83160887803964,-16.6521257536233,21.6214751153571));
#481=CARTESIAN_POINT('',(-5.65112668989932,-16.81623579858,21.5347348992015));
#482=CARTESIAN_POINT('',(-5.36383637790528,-17.0892441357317,21.3703228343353));
#483=CARTESIAN_POINT('',(-5.25283846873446,-17.1979482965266,21.2995904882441));
#484=CARTESIAN_POINT('',(-5.03791406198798,-17.4144388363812,21.1469047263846));
#485=CARTESIAN_POINT('',(-4.93398545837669,-17.522225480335,21.0649546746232));
#486=CARTESIAN_POINT('',(-4.73402726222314,-17.7352600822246,20.8896987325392));
#487=CARTESIAN_POINT('',(-4.63797997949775,-17.8405133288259,20.7964195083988));
#488=CARTESIAN_POINT('',(-4.45412221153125,-18.0471745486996,20.5982992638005));
#489=CARTESIAN_POINT('',(-4.36630734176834,-18.1485845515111,20.4934644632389));
#490=CARTESIAN_POINT('',(-4.22643837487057,-18.3139795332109,20.3082572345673));
#491=CARTESIAN_POINT('',(-4.17201918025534,-18.3794406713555,20.230970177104));
#492=CARTESIAN_POINT('',(-4.06726211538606,-18.5073995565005,20.0713415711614));
#493=CARTESIAN_POINT('',(-4.0169243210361,-18.5698972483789,19.9889999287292));
#494=CARTESIAN_POINT('',(-3.96868008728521,-18.6306715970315,19.9041996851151));
#495=B_SPLINE_CURVE_WITH_KNOTS('',3,(#449,#450,#451,#452,#453,#454,#455,#456,#457,#458,#459,
#460,#461,#462,#463,#464,#465,#466,#467,#468,#469,#470,#471,#472,#473,#474,#475,#476,#477,#478,
#479,#480,#481,#482,#483,#484,#485,#486,#487,#488,#489,#490,#491,#492,#493,#494),.UNSPECIFIED.,
.F.,.F.,(4,2,2,2,2,2,2,2,2,2,2,2,2,2,2,2,2,2,2,2,2,2,4),(0.,0.540908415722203,1.0811457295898,
1.61583448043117,2.15066622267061,2.68305208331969,3.21539915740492,3.74924927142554,
4.28321489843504,5.05152996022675,5.82012672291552,6.59017425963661,7.36013181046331,
8.13775079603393,8.91550787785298,9.69116096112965,10.4663026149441,10.9779647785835,
11.4894738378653,11.9998014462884,12.5098556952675,12.8545815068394,13.199313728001),.UNSPECIFIED.);
#496=CARTESIAN_POINT('',(-3.96883886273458,-18.6304715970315,19.9044786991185));
#497=VERTEX_POINT('',#496);
#498=EDGE_CURVE('E288',#446,#497,#495,.T.);
#499=ORIENTED_EDGE('',*,*,#498,.T.);
#500=CARTESIAN_POINT('',(-1.48805741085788,-19.94456530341,16.38093031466));
#501=CARTESIAN_POINT('',(-1.49147422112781,-19.944310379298,16.3853314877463));
#502=CARTESIAN_POINT('',(-1.4948907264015,-19.9440504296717,16.389732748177));
#503=CARTESIAN_POINT('',(-1.81379375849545,-19.9193149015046,16.8006005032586));
#504=CARTESIAN_POINT('',(-2.12658065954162,-19.8519874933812,17.2077752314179));
#505=CARTESIAN_POINT('',(-2.72890668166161,-19.6321878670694,18.017303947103));
#506=CARTESIAN_POINT('',(-3.01841511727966,-19.4796053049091,18.4196509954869));
#507=CARTESIAN_POINT('',(-3.41111362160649,-19.1940432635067,19.0006622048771));
#508=CARTESIAN_POINT('',(-3.53138560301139,-19.0939385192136,19.1842811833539));
#509=CARTESIAN_POINT('',(-3.7597845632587,-18.8756523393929,19.5475677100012));
#510=CARTESIAN_POINT('',(-3.86793749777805,-18.7575108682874,19.7272430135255));
#511=CARTESIAN_POINT('',(-3.96899762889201,-18.6302715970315,19.9047576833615));
#512=B_SPLINE_CURVE_WITH_KNOTS('',3,(#500,#501,#502,#503,#504,#505,#506,#507,#508,#509,#510,
#511),.UNSPECIFIED.,.F.,.F.,(4,2,2,2,2,4),(0.,0.0167332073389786,1.56205380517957,
3.10937912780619,3.83223807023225,4.5535179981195),.UNSPECIFIED.);
#513=EDGE_CURVE('E295',#130,#497,#512,.T.);
#514=ORIENTED_EDGE('',*,*,#513,.F.);
#515=ORIENTED_EDGE('',*,*,#131,.T.);
#516=CARTESIAN_POINT('',(3.96899762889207,-18.6302715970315,19.9047576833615));
#517=CARTESIAN_POINT('',(3.87488306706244,-18.7487894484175,19.7394301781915));
#518=CARTESIAN_POINT('',(3.77455997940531,-18.8594451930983,19.5721519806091));
#519=CARTESIAN_POINT('',(3.56354943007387,-19.0648747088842,19.2345672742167));
#520=CARTESIAN_POINT('',(3.45286825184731,-19.1596580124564,19.0642626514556));
#521=CARTESIAN_POINT('',(3.22337066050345,-19.3331052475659,18.7217368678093));
#522=CARTESIAN_POINT('',(3.10457584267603,-19.4118099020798,18.5495217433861));
#523=CARTESIAN_POINT('',(2.86030415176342,-19.5533565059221,18.2033602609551));
#524=CARTESIAN_POINT('',(2.73482744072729,-19.616198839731,18.0294139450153));
#525=CARTESIAN_POINT('',(2.42924956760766,-19.7472078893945,17.6128190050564));
#526=CARTESIAN_POINT('',(2.2467726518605,-19.8080525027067,17.3695899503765));
#527=CARTESIAN_POINT('',(1.8759796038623,-19.8989790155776,16.8822329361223));
#528=CARTESIAN_POINT('',(1.6876707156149,-19.9290976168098,16.6381063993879));
#529=CARTESIAN_POINT('',(1.49489075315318,-19.9440504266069,16.389732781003));
#530=CARTESIAN_POINT('',(1.49147424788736,-19.9443103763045,16.3853315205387));
#531=CARTESIAN_POINT('',(1.48805741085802,-19.94456530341,16.38093031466));
#532=B_SPLINE_CURVE_WITH_KNOTS('',3,(#516,#517,#518,#519,#520,#521,#522,#523,#524,#525,#526,
#527,#528,#529,#530,#531),.UNSPECIFIED.,.F.,.F.,(4,2,2,2,2,2,2,4),(0.,0.672016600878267,
1.34362815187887,2.01351700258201,2.68338961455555,3.61205098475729,4.53960178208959,
4.55633498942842),.UNSPECIFIED.);
#533=CARTESIAN_POINT('',(3.96883886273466,-18.6304715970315,19.9044786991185));
#534=VERTEX_POINT('',#533);
#535=EDGE_CURVE('E319',#534,#126,#532,.T.);
#536=ORIENTED_EDGE('',*,*,#535,.F.);
#537=CARTESIAN_POINT('',(3.96868008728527,-18.6306715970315,19.9041996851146));
#538=CARTESIAN_POINT('',(4.04437009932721,-18.5352984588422,20.0373324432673));
#539=CARTESIAN_POINT('',(4.12526413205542,-18.4356613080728,20.1643450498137));
#540=CARTESIAN_POINT('',(4.29682494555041,-18.2299121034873,20.4055808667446));
#541=CARTESIAN_POINT('',(4.38747947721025,-18.1238082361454,20.5198197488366));
#542=CARTESIAN_POINT('',(4.57713747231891,-17.9080462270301,20.734184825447));
#543=CARTESIAN_POINT('',(4.67604562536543,-17.7984357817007,20.8344439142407));
#544=CARTESIAN_POINT('',(4.88238077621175,-17.5763891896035,21.0223145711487));
#545=CARTESIAN_POINT('',(4.98981004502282,-17.4639522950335,21.1099227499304));
#546=CARTESIAN_POINT('',(5.21195811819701,-17.2384215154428,21.2724206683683));
#547=CARTESIAN_POINT('',(5.32664134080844,-17.1253329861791,21.3473667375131));
#548=CARTESIAN_POINT('',(5.56302161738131,-16.8994018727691,21.4855727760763));
#549=CARTESIAN_POINT('',(5.68471815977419,-16.7865592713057,21.5488335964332));
#550=CARTESIAN_POINT('',(5.93480326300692,-16.5619776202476,21.664519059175));
#551=CARTESIAN_POINT('',(6.06320974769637,-16.4502425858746,21.716912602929));
#552=CARTESIAN_POINT('',(6.32576627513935,-16.2291643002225,21.8113760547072));
#553=CARTESIAN_POINT('',(6.45991755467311,-16.1198215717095,21.8534437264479));
#554=CARTESIAN_POINT('',(6.79339160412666,-15.8570291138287,21.9443164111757));
#555=CARTESIAN_POINT('',(6.99547686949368,-15.7052831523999,21.9879752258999));
#556=CARTESIAN_POINT('',(7.40871955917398,-15.4101952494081,22.0571569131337));
#557=CARTESIAN_POINT('',(7.6198802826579,-15.2668564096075,22.0826731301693));
#558=CARTESIAN_POINT('',(8.05020035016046,-14.9896326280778,22.116750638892));
#559=CARTESIAN_POINT('',(8.26937403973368,-14.8557660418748,22.1252798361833));
#560=CARTESIAN_POINT('',(8.71390124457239,-14.59876043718,22.1256982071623));
#561=CARTESIAN_POINT('',(8.93925403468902,-14.4756201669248,22.1175893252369));
#562=CARTESIAN_POINT('',(9.39691071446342,-14.2396244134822,22.0841784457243));
#563=CARTESIAN_POINT('',(9.62926146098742,-14.1268834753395,22.058706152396));
#564=CARTESIAN_POINT('',(10.0969036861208,-13.9136966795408,21.9891901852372));
#565=CARTESIAN_POINT('',(10.3321956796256,-13.813253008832,21.9451432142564));
#566=CARTESIAN_POINT('',(10.8026152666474,-13.6254517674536,21.8367845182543));
#567=CARTESIAN_POINT('',(11.0377415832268,-13.538059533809,21.7725279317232));
#568=CARTESIAN_POINT('',(11.5052304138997,-13.37642671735,21.6215210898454));
#569=CARTESIAN_POINT('',(11.7375946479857,-13.3021775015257,21.5347856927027));
#570=CARTESIAN_POINT('',(12.1176745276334,-13.1898767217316,21.3703811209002));
#571=CARTESIAN_POINT('',(12.2673166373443,-13.1480997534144,21.2996511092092));
#572=CARTESIAN_POINT('',(12.5622706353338,-13.0702110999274,21.1469698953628));
#573=CARTESIAN_POINT('',(12.707583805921,-13.0340977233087,21.0650220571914));
#574=CARTESIAN_POINT('',(12.9920623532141,-12.9674425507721,20.8897703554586));
#575=CARTESIAN_POINT('',(13.1312411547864,-12.9368880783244,20.7964931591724));
#576=CARTESIAN_POINT('',(13.4021505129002,-12.8809899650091,20.5983767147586));
#577=CARTESIAN_POINT('',(13.5338850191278,-12.8556435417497,20.4935436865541));
#578=CARTESIAN_POINT('',(13.7470664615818,-12.817207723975,20.3083350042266));
#579=CARTESIAN_POINT('',(13.8309740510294,-12.8028082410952,20.2310445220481));
#580=CARTESIAN_POINT('',(13.9941817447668,-12.7760624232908,20.0714083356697));
#581=CARTESIAN_POINT('',(14.0734817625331,-12.7637161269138,19.9890625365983));
#582=CARTESIAN_POINT('',(14.1502422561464,-12.7523213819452,19.9042577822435));
#583=B_SPLINE_CURVE_WITH_KNOTS('',3,(#537,#538,#539,#540,#541,#542,#543,#544,#545,#546,#547,
#548,#549,#550,#551,#552,#553,#554,#555,#556,#557,#558,#559,#560,#561,#562,#563,#564,#565,#566,
#567,#568,#569,#570,#571,#572,#573,#574,#575,#576,#577,#578,#579,#580,#581,#582),.UNSPECIFIED.,
.F.,.F.,(4,2,2,2,2,2,2,2,2,2,2,2,2,2,2,2,2,2,2,2,2,2,4),(0.,0.540904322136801,1.08113756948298,
1.61582234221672,2.15065009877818,2.68303208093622,3.21537527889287,3.74922146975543,
4.28318317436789,5.05149336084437,5.82008525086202,6.59012790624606,7.36008057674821,
8.13769549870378,8.91544851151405,9.69109770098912,10.4662354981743,10.9779030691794,
11.4894175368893,11.9997505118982,12.5098101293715,12.854558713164,13.1993137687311),.UNSPECIFIED.);
#584=CARTESIAN_POINT('',(14.1500422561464,-12.752351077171,19.9044786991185));
#585=VERTEX_POINT('',#584);
#586=EDGE_CURVE('E325',#534,#585,#583,.T.);
#587=ORIENTED_EDGE('',*,*,#586,.T.);
#588=CARTESIAN_POINT('',(16.5284715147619,-11.2609781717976,16.38093031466));
#589=CARTESIAN_POINT('',(16.5265423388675,-11.2638097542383,16.385331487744));
#590=CARTESIAN_POINT('',(16.5246089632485,-11.2666385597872,16.3897327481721));
#591=CARTESIAN_POINT('',(16.3437358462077,-11.5304489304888,16.8006005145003));
#592=CARTESIAN_POINT('',(16.1290351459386,-11.7676666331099,17.2077752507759));
#593=CARTESIAN_POINT('',(15.6375200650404,-12.1793964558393,18.0173039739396));
#594=CARTESIAN_POINT('',(15.3606254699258,-12.3538268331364,18.4196510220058));
#595=CARTESIAN_POINT('',(14.916979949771,-12.5511292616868,19.0006521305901));
#596=CARTESIAN_POINT('',(14.7701590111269,-12.6052330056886,19.1842611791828));
#597=CARTESIAN_POINT('',(14.4669357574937,-12.6938865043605,19.5475282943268));
#598=CARTESIAN_POINT('',(14.3105550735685,-12.7284787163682,19.7271941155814));
#599=CARTESIAN_POINT('',(14.1498422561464,-12.7523807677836,19.9046996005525));
#600=B_SPLINE_CURVE_WITH_KNOTS('',3,(#588,#589,#590,#591,#592,#593,#594,#595,#596,#597,#598,
#599),.UNSPECIFIED.,.F.,.F.,(4,2,2,2,2,4),(0.,0.0167332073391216,1.56205384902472,
3.1093791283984,3.83219873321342,4.55343934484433),.UNSPECIFIED.);
#601=EDGE_CURVE('E332',#103,#585,#600,.T.);
#602=ORIENTED_EDGE('',*,*,#601,.F.);
#603=ORIENTED_EDGE('',*,*,#104,.T.);
#604=CARTESIAN_POINT('',(18.1188021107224,-5.87792051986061,19.9047136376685));
#605=CARTESIAN_POINT('',(18.174382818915,-6.01868604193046,19.7393849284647));
#606=CARTESIAN_POINT('',(18.2200504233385,-6.16089717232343,19.5721055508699));
#607=CARTESIAN_POINT('',(18.2924491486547,-6.44635409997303,19.23451852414));
#608=CARTESIAN_POINT('',(18.3191916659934,-6.58959922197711,19.0642127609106));
#609=CARTESIAN_POINT('',(18.3546491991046,-6.87507491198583,18.7216847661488));
#610=CARTESIAN_POINT('',(18.3634102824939,-7.01730713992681,18.5494685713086));
#611=CARTESIAN_POINT('',(18.3638538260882,-7.29962689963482,18.2033049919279));
#612=CARTESIAN_POINT('',(18.3555367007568,-7.43971448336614,18.0293576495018));
#613=CARTESIAN_POINT('',(18.3162014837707,-7.76984941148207,17.6127710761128));
#614=CARTESIAN_POINT('',(18.2776557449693,-7.9582933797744,17.3695515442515));
#615=CARTESIAN_POINT('',(18.171005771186,-8.32485756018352,16.882213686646));
#616=CARTESIAN_POINT('',(18.1029369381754,-8.50298984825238,16.6380967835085));
#617=CARTESIAN_POINT('',(18.0194997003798,-8.67741184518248,16.3897327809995));
#618=CARTESIAN_POINT('',(18.0180165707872,-8.68050060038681,16.3853315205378));
#619=CARTESIAN_POINT('',(18.0165289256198,-8.68358713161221,16.38093031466));
#620=B_SPLINE_CURVE_WITH_KNOTS('',3,(#604,#605,#606,#607,#608,#609,#610,#611,#612,#613,#614,
#615,#616,#617,#618,#619),.UNSPECIFIED.,.F.,.F.,(4,2,2,2,2,2,2,4),(0.,0.6720200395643,
1.34363505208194,2.0135272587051,2.68340320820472,3.61202792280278,4.53954216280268,
4.55627537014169),.UNSPECIFIED.);
#621=CARTESIAN_POINT('',(18.118881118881,-5.87812051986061,19.9044786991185));
#622=VERTEX_POINT('',#621);
#623=EDGE_CURVE('E338',#622,#99,#620,.T.);
#624=ORIENTED_EDGE('',*,*,#623,.F.);
#625=CARTESIAN_POINT('',(18.1189601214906,-5.87832051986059,19.9042437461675));
#626=CARTESIAN_POINT('',(18.0742090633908,-5.76508237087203,20.037375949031));
#627=CARTESIAN_POINT('',(18.0283673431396,-5.64520539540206,20.1643878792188));
#628=CARTESIAN_POINT('',(17.9359630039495,-5.39375057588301,20.4056221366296));
#629=CARTESIAN_POINT('',(17.8894013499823,-5.26218743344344,20.5198601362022));
#630=CARTESIAN_POINT('',(17.7973745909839,-4.99005371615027,20.73422328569));
#631=CARTESIAN_POINT('',(17.7519031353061,-4.849589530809,20.8344813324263));
#632=CARTESIAN_POINT('',(17.6627726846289,-4.5598708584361,21.0223497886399));
#633=CARTESIAN_POINT('',(17.619114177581,-4.41061403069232,21.1099568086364));
#634=CARTESIAN_POINT('',(17.5348731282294,-4.10545908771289,21.2724523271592));
#635=CARTESIAN_POINT('',(17.4942774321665,-3.94959446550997,21.3473971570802));
#636=CARTESIAN_POINT('',(17.4168061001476,-3.6319141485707,21.4856006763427));
#637=CARTESIAN_POINT('',(17.3799301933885,-3.47009888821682,21.54886021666));
#638=CARTESIAN_POINT('',(17.3104802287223,-3.14122478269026,21.6645431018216));
#639=CARTESIAN_POINT('',(17.2779186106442,-2.97415242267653,21.7169353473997));
#640=CARTESIAN_POINT('',(17.2177386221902,-2.63622963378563,21.8113961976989));
#641=CARTESIAN_POINT('',(17.1901213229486,-2.46537839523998,21.8534625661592));
#642=CARTESIAN_POINT('',(17.1292751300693,-2.04518192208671,21.9443320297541));
#643=CARTESIAN_POINT('',(17.0989030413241,-1.79429623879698,21.9879889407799));
#644=CARTESIAN_POINT('',(17.0499732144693,-1.28887036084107,22.0571668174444));
#645=CARTESIAN_POINT('',(17.0314198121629,-1.0343288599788,22.0826811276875));
#646=CARTESIAN_POINT('',(17.0064997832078,-0.523045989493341,22.1167547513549));
#647=CARTESIAN_POINT('',(17.0001562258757,-0.266301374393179,22.1252819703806));
#648=CARTESIAN_POINT('',(16.9998494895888,0.24717575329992,22.125696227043));
#649=CARTESIAN_POINT('',(17.0058848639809,0.503908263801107,22.1175852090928));
#650=CARTESIAN_POINT('',(17.0303381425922,1.01825026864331,22.0841697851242));
#651=CARTESIAN_POINT('',(17.0488786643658,1.27584306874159,22.0586950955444));
#652=CARTESIAN_POINT('',(17.098077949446,1.78742757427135,21.9891739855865));
#653=CARTESIAN_POINT('',(17.128738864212,2.04141863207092,21.9451242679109));
#654=CARTESIAN_POINT('',(17.2013113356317,2.54271489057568,21.8367596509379));
#655=CARTESIAN_POINT('',(17.2431922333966,2.79003631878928,21.7724998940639));
#656=CARTESIAN_POINT('',(17.3369616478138,3.27570930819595,21.6214862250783));
#657=CARTESIAN_POINT('',(17.3888435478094,3.51406667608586,21.5347471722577));
#658=CARTESIAN_POINT('',(17.4816300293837,3.89937284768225,21.3703368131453));
#659=CARTESIAN_POINT('',(17.5202715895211,4.04985295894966,21.2996049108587));
#660=CARTESIAN_POINT('',(17.6002956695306,4.34423029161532,21.1469199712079));
#661=CARTESIAN_POINT('',(17.6416773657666,4.48812946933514,21.0649702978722));
#662=CARTESIAN_POINT('',(17.7261917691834,4.767817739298,20.8897150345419));
#663=CARTESIAN_POINT('',(17.769320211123,4.90362479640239,20.796436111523));
#664=CARTESIAN_POINT('',(17.8563654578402,5.16618299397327,20.5983163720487));
#665=CARTESIAN_POINT('',(17.9002818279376,5.29293894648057,20.4934817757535));
#666=CARTESIAN_POINT('',(17.9735824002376,5.49676399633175,20.3082786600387));
#667=CARTESIAN_POINT('',(18.0030624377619,5.57661965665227,20.23099580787));
#668=CARTESIAN_POINT('',(18.0614968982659,5.73131526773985,20.0713760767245));
#669=CARTESIAN_POINT('',(18.0904513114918,5.80615512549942,19.9890391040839));
#670=CARTESIAN_POINT('',(18.1189601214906,5.87832051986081,19.9042437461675));
#671=B_SPLINE_CURVE_WITH_KNOTS('',3,(#625,#626,#627,#628,#629,#630,#631,#632,#633,#634,#635,
#636,#637,#638,#639,#640,#641,#642,#643,#644,#645,#646,#647,#648,#649,#650,#651,#652,#653,#654,
#655,#656,#657,#658,#659,#660,#661,#662,#663,#664,#665,#666,#667,#668,#669,#670),.UNSPECIFIED.,
.F.,.F.,(4,2,2,2,2,2,2,2,2,2,2,2,2,2,2,2,2,2,2,2,2,2,4),(0.,0.540907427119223,1.08114375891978,
1.61583154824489,2.15066232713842,2.68304725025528,3.21539338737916,3.74924255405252,
4.28320723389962,5.05152112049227,5.82011670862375,6.59016306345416,7.36011943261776,
8.13773742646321,8.91549351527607,9.69114566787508,10.4662863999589,10.9779506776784,
11.4894618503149,11.9997915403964,12.509847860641,12.8545572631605,13.1992730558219),.UNSPECIFIED.);
#672=CARTESIAN_POINT('',(18.118881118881,5.87812051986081,19.9044786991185));
#673=VERTEX_POINT('',#672);
#674=EDGE_CURVE('E362',#622,#673,#671,.T.);
#675=ORIENTED_EDGE('',*,*,#674,.T.);
#676=CARTESIAN_POINT('',(18.0165289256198,8.68358713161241,16.38093031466));
#677=CARTESIAN_POINT('',(18.0180165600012,8.6805006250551,16.3853314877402));
#678=CARTESIAN_POINT('',(18.0194996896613,8.67741186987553,16.3897327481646));
#679=CARTESIAN_POINT('',(18.157529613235,8.38886597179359,16.8006005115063));
#680=CARTESIAN_POINT('',(18.2556158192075,8.08432086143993,17.2077752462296));
#681=CARTESIAN_POINT('',(18.3664267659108,7.45279140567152,18.017303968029));
#682=CARTESIAN_POINT('',(18.3790406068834,7.12577846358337,18.4196510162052));
#683=CARTESIAN_POINT('',(18.3280865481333,6.64291692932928,19.0006545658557));
#684=CARTESIAN_POINT('',(18.3015308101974,6.48871235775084,19.1842660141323));
#685=CARTESIAN_POINT('',(18.2266938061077,6.18178255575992,19.5475378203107));
#686=CARTESIAN_POINT('',(18.1784601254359,6.0290548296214,19.7272059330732));
#687=CARTESIAN_POINT('',(18.1188021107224,5.8779205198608,19.9047136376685));
#688=B_SPLINE_CURVE_WITH_KNOTS('',3,(#676,#677,#678,#679,#680,#681,#682,#683,#684,#685,#686,
#687),.UNSPECIFIED.,.F.,.F.,(4,2,2,2,2,4),(0.,0.0167332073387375,1.5620538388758,
3.1093791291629,3.83220824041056,4.55345835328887),.UNSPECIFIED.);
#689=EDGE_CURVE('E369',#76,#673,#688,.T.);
#690=ORIENTED_EDGE('',*,*,#689,.F.);
#691=ORIENTED_EDGE('',*,*,#77,.T.);
#692=CARTESIAN_POINT('',(14.1498422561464,12.7523807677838,19.9046996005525));
#693=CARTESIAN_POINT('',(14.2995391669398,12.7301317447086,19.7393705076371));
#694=CARTESIAN_POINT('',(14.4455314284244,12.6985749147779,19.5720907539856));
#695=CARTESIAN_POINT('',(14.7289436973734,12.6185444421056,19.2345029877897));
#696=CARTESIAN_POINT('',(14.866368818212,12.570081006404,19.0641968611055));
#697=CARTESIAN_POINT('',(15.1313266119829,12.4580491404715,18.7216681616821));
#698=CARTESIAN_POINT('',(15.2588837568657,12.3945197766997,18.5494516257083));
#699=CARTESIAN_POINT('',(15.5036013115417,12.2537428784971,18.2032873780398));
#700=CARTESIAN_POINT('',(15.6207619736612,12.1764956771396,18.0293397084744));
#701=CARTESIAN_POINT('',(15.8869968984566,11.9773632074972,17.6127558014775));
#702=CARTESIAN_POINT('',(16.0309190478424,11.8497608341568,17.3695393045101));
#703=CARTESIAN_POINT('',(16.2950440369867,11.5741201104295,16.8822075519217));
#704=CARTESIAN_POINT('',(16.4152750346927,11.4261063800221,16.6380937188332));
#705=CARTESIAN_POINT('',(16.5246089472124,11.2666385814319,16.3897327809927));
#706=CARTESIAN_POINT('',(16.5265423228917,11.2638097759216,16.3853315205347));
#707=CARTESIAN_POINT('',(16.5284715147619,11.2609781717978,16.38093031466));
#708=B_SPLINE_CURVE_WITH_KNOTS('',3,(#692,#693,#694,#695,#696,#697,#698,#699,#700,#701,#702,
#703,#704,#705,#706,#707),.UNSPECIFIED.,.F.,.F.,(4,2,2,2,2,2,2,4),(0.,0.672021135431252,
1.34363725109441,2.01353052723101,2.68340754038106,3.61202057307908,4.53952316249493,
4.55625636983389),.UNSPECIFIED.);
#709=CARTESIAN_POINT('',(14.1500422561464,12.752351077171,19.9044786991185));
#710=VERTEX_POINT('',#709);
#711=EDGE_CURVE('E375',#710,#72,#708,.T.);
#712=ORIENTED_EDGE('',*,*,#711,.F.);
#713=CARTESIAN_POINT('',(14.1502422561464,12.7523213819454,19.9042577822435));
#714=CARTESIAN_POINT('',(14.0297989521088,12.7701850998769,20.0373898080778));
#715=CARTESIAN_POINT('',(13.903060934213,12.7904237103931,20.1644015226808));
#716=CARTESIAN_POINT('',(13.6390912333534,12.8361270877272,20.4056352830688));
#717=CARTESIAN_POINT('',(13.5018727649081,12.8615853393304,20.5198730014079));
#718=CARTESIAN_POINT('',(13.2201834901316,12.9179552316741,20.7342355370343));
#719=CARTESIAN_POINT('',(13.075801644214,12.9488081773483,20.8344932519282));
#720=CARTESIAN_POINT('',(12.7803316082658,13.016478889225,21.0223610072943));
#721=CARTESIAN_POINT('',(12.6292416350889,13.0532982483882,21.1099676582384));
#722=CARTESIAN_POINT('',(12.3228482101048,13.1329214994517,21.2724624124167));
#723=CARTESIAN_POINT('',(12.1675671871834,13.1756972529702,21.3474068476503));
#724=CARTESIAN_POINT('',(11.8537114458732,13.2674459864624,21.4856095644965));
#725=CARTESIAN_POINT('',(11.6951369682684,13.316418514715,21.5488686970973));
#726=CARTESIAN_POINT('',(11.3755979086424,13.4207108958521,21.6645507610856));
#727=CARTESIAN_POINT('',(11.2146278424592,13.4760482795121,21.7169425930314));
#728=CARTESIAN_POINT('',(10.8918874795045,13.5928930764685,21.8114026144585));
#729=CARTESIAN_POINT('',(10.7301170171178,13.6544018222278,21.8534685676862));
#730=CARTESIAN_POINT('',(10.3357924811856,13.8118067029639,21.9443370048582));
#731=CARTESIAN_POINT('',(10.1033327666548,13.9109471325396,21.9879933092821));
#732=CARTESIAN_POINT('',(9.64115569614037,14.1212867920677,22.0571699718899));
#733=CARTESIAN_POINT('',(9.41143937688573,14.2324904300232,22.0826836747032));
#734=CARTESIAN_POINT('',(8.9561950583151,14.4665517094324,22.1167560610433));
#735=CARTESIAN_POINT('',(8.73067578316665,14.5894309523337,22.1252826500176));
#736=CARTESIAN_POINT('',(8.28583797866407,14.845905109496,22.1256955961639));
#737=CARTESIAN_POINT('',(8.06651872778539,14.9794987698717,22.1175838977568));
#738=CARTESIAN_POINT('',(7.63331213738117,15.257848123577,22.084167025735));
#739=CARTESIAN_POINT('',(7.4195005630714,15.4027016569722,22.0586915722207));
#740=CARTESIAN_POINT('',(7.00105526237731,15.7011028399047,21.9891688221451));
#741=CARTESIAN_POINT('',(6.79642317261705,15.8546520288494,21.94511822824));
#742=CARTESIAN_POINT('',(6.39857455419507,16.1681507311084,21.8367517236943));
#743=CARTESIAN_POINT('',(6.20532864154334,16.328081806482,21.7724909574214));
#744=CARTESIAN_POINT('',(5.83160887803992,16.6521257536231,21.6214751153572));
#745=CARTESIAN_POINT('',(5.6511266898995,16.8162357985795,21.5347348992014));
#746=CARTESIAN_POINT('',(5.3638363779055,17.0892441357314,21.3703228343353));
#747=CARTESIAN_POINT('',(5.25283846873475,17.1979482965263,21.2995904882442));
#748=CARTESIAN_POINT('',(5.03791406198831,17.414438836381,21.1469047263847));
#749=CARTESIAN_POINT('',(4.93398545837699,17.5222254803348,21.0649546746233));
#750=CARTESIAN_POINT('',(4.73402726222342,17.7352600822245,20.8896987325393));
#751=CARTESIAN_POINT('',(4.63797997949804,17.8405133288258,20.796419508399));
#752=CARTESIAN_POINT('',(4.45412221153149,18.0471745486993,20.5982992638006));
#753=CARTESIAN_POINT('',(4.3663073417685,18.1485845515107,20.4934644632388));
#754=CARTESIAN_POINT('',(4.22643837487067,18.3139795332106,20.3082572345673));
#755=CARTESIAN_POINT('',(4.17201918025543,18.3794406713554,20.230970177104));
#756=CARTESIAN_POINT('',(4.06726211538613,18.5073995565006,20.0713415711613));
#757=CARTESIAN_POINT('',(4.01692432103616,18.5698972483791,19.988999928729));
#758=CARTESIAN_POINT('',(3.96868008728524,18.6306715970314,19.9041996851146));
#759=B_SPLINE_CURVE_WITH_KNOTS('',3,(#713,#714,#715,#716,#717,#718,#719,#720,#721,#722,#723,
#724,#725,#726,#727,#728,#729,#730,#731,#732,#733,#734,#735,#736,#737,#738,#739,#740,#741,#742,
#743,#744,#745,#746,#747,#748,#749,#750,#751,#752,#753,#754,#755,#756,#757,#758),.UNSPECIFIED.,
.F.,.F.,(4,2,2,2,2,2,2,2,2,2,2,2,2,2,2,2,2,2,2,2,2,2,4),(0.,0.540908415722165,1.08114572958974,
1.61583448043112,2.15066622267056,2.68305208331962,3.21539915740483,3.74924927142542,
4.28321489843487,5.05152996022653,5.82012672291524,6.59017425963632,7.36013181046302,
8.1377507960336,8.91550787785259,9.69116096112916,10.4663026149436,10.977964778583,
11.4894738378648,11.9998014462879,12.509855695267,12.8545815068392,13.1993137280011),.UNSPECIFIED.);
#760=EDGE_CURVE('E205',#710,#248,#759,.T.);
#761=ORIENTED_EDGE('',*,*,#760,.T.);
#762=EDGE_LOOP('',(#250,#251,#272,#323,#338,#339,#360,#411,#426,#427,#448,#499,#514,#515,#536,
#587,#602,#603,#624,#675,#690,#691,#712,#761));
#763=FACE_BOUND('',#762,.T.);
#764=ORIENTED_EDGE('',*,*,#213,.F.);
#765=EDGE_LOOP('',(#764));
#766=FACE_BOUND('',#765,.T.);
#767=ADVANCED_FACE('F195',(#763,#766),#233,.T.);
#768=CARTESIAN_POINT('',(0.,9.,12.9999999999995));
#769=DIRECTION('',(0.,0.,1.));
#770=DIRECTION('',(-1.,0.,0.));
#771=AXIS2_PLACEMENT_3D('',#768,#769,#770);
#772=PLANE('',#771);
#773=ORIENTED_EDGE('',*,*,#33,.F.);
#774=CARTESIAN_POINT('',(1.22764736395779,16.4542663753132,12.9999999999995));
#775=DIRECTION('',(0.,0.,1.));
#776=DIRECTION('',(-1.,0.,0.));
#777=AXIS2_PLACEMENT_3D('',#774,#775,#776);
#778=CIRCLE('',#777,3.5);
#779=CARTESIAN_POINT('',(3.96883886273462,18.6304715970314,12.9999999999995));
#780=VERTEX_POINT('',#779);
#781=EDGE_CURVE('E9',#30,#780,#778,.F.);
#782=ORIENTED_EDGE('',*,*,#781,.T.);
#783=CARTESIAN_POINT('',(16.5,28.5788383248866,12.9999999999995));
#784=DIRECTION('',(0.,0.,1.));
#785=DIRECTION('',(-1.,0.,0.));
#786=AXIS2_PLACEMENT_3D('',#783,#784,#785);
#787=CIRCLE('',#786,16.);
#788=CARTESIAN_POINT('',(14.1500422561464,12.752351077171,12.9999999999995));
#789=VERTEX_POINT('',#788);
#790=EDGE_CURVE('E22',#789,#780,#787,.F.);
#791=ORIENTED_EDGE('',*,*,#790,.F.);
#792=CARTESIAN_POINT('',(13.6359889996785,9.290306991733,12.9999999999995));
#793=DIRECTION('',(0.,0.,1.));
#794=DIRECTION('',(-1.,0.,0.));
#795=AXIS2_PLACEMENT_3D('',#792,#793,#794);
#796=CIRCLE('',#795,3.5);
#797=EDGE_CURVE('E501',#789,#64,#796,.F.);
#798=ORIENTED_EDGE('',*,*,#797,.T.);
#799=ORIENTED_EDGE('',*,*,#65,.F.);
#800=CARTESIAN_POINT('',(14.8636363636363,7.16395938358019,12.9999999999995));
#801=DIRECTION('',(0.,0.,1.));
#802=DIRECTION('',(-1.,0.,0.));
#803=AXIS2_PLACEMENT_3D('',#800,#801,#802);
#804=CIRCLE('',#803,3.5);
#805=CARTESIAN_POINT('',(18.118881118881,5.87812051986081,12.9999999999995));
#806=VERTEX_POINT('',#805);
#807=EDGE_CURVE('E499',#62,#806,#804,.F.);
#808=ORIENTED_EDGE('',*,*,#807,.T.);
#809=CARTESIAN_POINT('',(33.,0.,12.9999999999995));
#810=DIRECTION('',(0.,0.,1.));
#811=DIRECTION('',(-1.,0.,0.));
#812=AXIS2_PLACEMENT_3D('',#809,#810,#811);
#813=CIRCLE('',#812,16.);
#814=CARTESIAN_POINT('',(18.118881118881,-5.87812051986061,12.9999999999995));
#815=VERTEX_POINT('',#814);
#816=EDGE_CURVE('E505',#815,#806,#813,.F.);
#817=ORIENTED_EDGE('',*,*,#816,.F.);
#818=CARTESIAN_POINT('',(14.8636363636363,-7.16395938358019,12.9999999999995));
#819=DIRECTION('',(0.,0.,1.));
#820=DIRECTION('',(-1.,0.,0.));
#821=AXIS2_PLACEMENT_3D('',#818,#819,#820);
#822=CIRCLE('',#821,3.5);
#823=EDGE_CURVE('E509',#815,#91,#822,.F.);
#824=ORIENTED_EDGE('',*,*,#823,.T.);
#825=ORIENTED_EDGE('',*,*,#92,.F.);
#826=CARTESIAN_POINT('',(13.6359889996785,-9.290306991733,12.9999999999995));
#827=DIRECTION('',(0.,0.,1.));
#828=DIRECTION('',(-1.,0.,0.));
#829=AXIS2_PLACEMENT_3D('',#826,#827,#828);
#830=CIRCLE('',#829,3.5);
#831=CARTESIAN_POINT('',(14.1500422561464,-12.752351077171,12.9999999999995));
#832=VERTEX_POINT('',#831);
#833=EDGE_CURVE('E512',#89,#832,#830,.F.);
#834=ORIENTED_EDGE('',*,*,#833,.T.);
#835=CARTESIAN_POINT('',(16.5,-28.5788383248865,12.9999999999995));
#836=DIRECTION('',(0.,0.,1.));
#837=DIRECTION('',(-1.,0.,0.));
#838=AXIS2_PLACEMENT_3D('',#835,#836,#837);
#839=CIRCLE('',#838,16.);
#840=CARTESIAN_POINT('',(3.96883886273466,-18.6304715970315,12.9999999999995));
#841=VERTEX_POINT('',#840);
#842=EDGE_CURVE('E515',#841,#832,#839,.F.);
#843=ORIENTED_EDGE('',*,*,#842,.F.);
#844=CARTESIAN_POINT('',(1.22764736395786,-16.4542663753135,12.9999999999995));
#845=DIRECTION('',(0.,0.,1.));
#846=DIRECTION('',(-1.,0.,0.));
#847=AXIS2_PLACEMENT_3D('',#844,#845,#846);
#848=CIRCLE('',#847,3.5);
#849=EDGE_CURVE('E517',#841,#118,#848,.F.);
#850=ORIENTED_EDGE('',*,*,#849,.T.);
#851=ORIENTED_EDGE('',*,*,#119,.F.);
#852=CARTESIAN_POINT('',(-1.22764736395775,-16.4542663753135,12.9999999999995));
#853=DIRECTION('',(0.,0.,1.));
#854=DIRECTION('',(-1.,0.,0.));
#855=AXIS2_PLACEMENT_3D('',#852,#853,#854);
#856=CIRCLE('',#855,3.5);
#857=CARTESIAN_POINT('',(-3.96883886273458,-18.6304715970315,12.9999999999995));
#858=VERTEX_POINT('',#857);
#859=EDGE_CURVE('E520',#116,#858,#856,.F.);
#860=ORIENTED_EDGE('',*,*,#859,.T.);
#861=CARTESIAN_POINT('',(-16.5,-28.5788383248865,12.9999999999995));
#862=DIRECTION('',(0.,0.,1.));
#863=DIRECTION('',(-1.,0.,0.));
#864=AXIS2_PLACEMENT_3D('',#861,#862,#863);
#865=CIRCLE('',#864,16.);
#866=CARTESIAN_POINT('',(-14.1500422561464,-12.752351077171,12.9999999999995));
#867=VERTEX_POINT('',#866);
#868=EDGE_CURVE('E523',#867,#858,#865,.F.);
#869=ORIENTED_EDGE('',*,*,#868,.F.);
#870=CARTESIAN_POINT('',(-13.6359889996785,-9.290306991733,12.9999999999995));
#871=DIRECTION('',(0.,0.,1.));
#872=DIRECTION('',(-1.,0.,0.));
#873=AXIS2_PLACEMENT_3D('',#870,#871,#872);
#874=CIRCLE('',#873,3.5);
#875=EDGE_CURVE('E525',#867,#145,#874,.F.);
#876=ORIENTED_EDGE('',*,*,#875,.T.);
#877=ORIENTED_EDGE('',*,*,#146,.F.);
#878=CARTESIAN_POINT('',(-14.8636363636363,-7.16395938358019,12.9999999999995));
#879=DIRECTION('',(0.,0.,1.));
#880=DIRECTION('',(-1.,0.,0.));
#881=AXIS2_PLACEMENT_3D('',#878,#879,#880);
#882=CIRCLE('',#881,3.5);
#883=CARTESIAN_POINT('',(-18.118881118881,-5.87812051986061,12.9999999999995));
#884=VERTEX_POINT('',#883);
#885=EDGE_CURVE('E528',#143,#884,#882,.F.);
#886=ORIENTED_EDGE('',*,*,#885,.T.);
#887=CARTESIAN_POINT('',(-33.,0.,12.9999999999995));
#888=DIRECTION('',(0.,0.,1.));
#889=DIRECTION('',(-1.,0.,0.));
#890=AXIS2_PLACEMENT_3D('',#887,#888,#889);
#891=CIRCLE('',#890,16.);
#892=CARTESIAN_POINT('',(-18.118881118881,5.87812051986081,12.9999999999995));
#893=VERTEX_POINT('',#892);
#894=EDGE_CURVE('E531',#893,#884,#891,.F.);
#895=ORIENTED_EDGE('',*,*,#894,.F.);
#896=CARTESIAN_POINT('',(-14.8636363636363,7.16395938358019,12.9999999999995));
#897=DIRECTION('',(0.,0.,1.));
#898=DIRECTION('',(-1.,0.,0.));
#899=AXIS2_PLACEMENT_3D('',#896,#897,#898);
#900=CIRCLE('',#899,3.5);
#901=EDGE_CURVE('E533',#893,#172,#900,.F.);
#902=ORIENTED_EDGE('',*,*,#901,.T.);
#903=ORIENTED_EDGE('',*,*,#173,.F.);
#904=CARTESIAN_POINT('',(-13.6359889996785,9.290306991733,12.9999999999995));
#905=DIRECTION('',(0.,0.,1.));
#906=DIRECTION('',(-1.,0.,0.));
#907=AXIS2_PLACEMENT_3D('',#904,#905,#906);
#908=CIRCLE('',#907,3.5);
#909=CARTESIAN_POINT('',(-14.1500422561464,12.7523510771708,12.9999999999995));
#910=VERTEX_POINT('',#909);
#911=EDGE_CURVE('E536',#170,#910,#908,.F.);
#912=ORIENTED_EDGE('',*,*,#911,.T.);
#913=CARTESIAN_POINT('',(-16.5,28.5788383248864,12.9999999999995));
#914=DIRECTION('',(0.,0.,1.));
#915=DIRECTION('',(-1.,0.,0.));
#916=AXIS2_PLACEMENT_3D('',#913,#914,#915);
#917=CIRCLE('',#916,16.);
#918=CARTESIAN_POINT('',(-3.96883886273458,18.6304715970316,12.9999999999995));
#919=VERTEX_POINT('',#918);
#920=EDGE_CURVE('E538',#919,#910,#917,.F.);
#921=ORIENTED_EDGE('',*,*,#920,.F.);
#922=CARTESIAN_POINT('',(-1.22764736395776,16.4542663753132,12.9999999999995));
#923=DIRECTION('',(0.,0.,1.));
#924=DIRECTION('',(-1.,0.,0.));
#925=AXIS2_PLACEMENT_3D('',#922,#923,#924);
#926=CIRCLE('',#925,3.5);
#927=EDGE_CURVE('E189',#919,#32,#926,.F.);
#928=ORIENTED_EDGE('',*,*,#927,.T.);
#929=EDGE_LOOP('',(#773,#782,#791,#798,#799,#808,#817,#824,#825,#834,#843,#850,#851,#860,#869,
#876,#877,#886,#895,#902,#903,#912,#921,#928));
#930=FACE_BOUND('',#929,.T.);
#931=CARTESIAN_POINT('',(0.,0.,12.9999999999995));
#932=DIRECTION('',(0.,0.,1.));
#933=DIRECTION('',(-1.,0.,0.));
#934=AXIS2_PLACEMENT_3D('',#931,#932,#933);
#935=CIRCLE('',#934,9.);
#936=CARTESIAN_POINT('',(-9.,0.,12.9999999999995));
#937=VERTEX_POINT('',#936);
#938=EDGE_CURVE('E460',#937,#937,#935,.T.);
#939=ORIENTED_EDGE('',*,*,#938,.T.);
#940=EDGE_LOOP('',(#939));
#941=FACE_BOUND('',#940,.T.);
#942=ADVANCED_FACE('F424',(#930,#941),#772,.F.);
#943=CARTESIAN_POINT('',(0.,0.,35.0080113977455));
#944=DIRECTION('',(0.,0.,1.));
#945=DIRECTION('',(-1.,0.,0.));
#946=AXIS2_PLACEMENT_3D('',#943,#944,#945);
#947=CYLINDRICAL_SURFACE('',#946,9.);
#948=CARTESIAN_POINT('',(0.,0.,10.9999999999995));
#949=DIRECTION('',(0.,0.,1.));
#950=DIRECTION('',(-1.,0.,0.));
#951=AXIS2_PLACEMENT_3D('',#948,#949,#950);
#952=CIRCLE('',#951,9.);
#953=CARTESIAN_POINT('',(-9.,0.,10.9999999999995));
#954=VERTEX_POINT('',#953);
#955=EDGE_CURVE('E465',#954,#954,#952,.T.);
#956=ORIENTED_EDGE('',*,*,#955,.T.);
#957=EDGE_LOOP('',(#956));
#958=FACE_BOUND('',#957,.T.);
#959=ORIENTED_EDGE('',*,*,#938,.F.);
#960=EDGE_LOOP('',(#959));
#961=FACE_BOUND('',#960,.T.);
#962=ADVANCED_FACE('F420',(#958,#961),#947,.T.);
#963=CARTESIAN_POINT('',(0.,7.,10.9999999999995));
#964=DIRECTION('',(0.,0.,1.));
#965=DIRECTION('',(-1.,0.,0.));
#966=AXIS2_PLACEMENT_3D('',#963,#964,#965);
#967=PLANE('',#966);
#968=ORIENTED_EDGE('',*,*,#955,.F.);
#969=EDGE_LOOP('',(#968));
#970=FACE_BOUND('',#969,.T.);
#971=CARTESIAN_POINT('',(0.,0.,10.9999999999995));
#972=DIRECTION('',(0.,0.,1.));
#973=DIRECTION('',(-1.,0.,0.));
#974=AXIS2_PLACEMENT_3D('',#971,#972,#973);
#975=CIRCLE('',#974,7.);
#976=CARTESIAN_POINT('',(-7.,0.,10.9999999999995));
#977=VERTEX_POINT('',#976);
#978=EDGE_CURVE('E869',#977,#977,#975,.T.);
#979=ORIENTED_EDGE('',*,*,#978,.T.);
#980=EDGE_LOOP('',(#979));
#981=FACE_BOUND('',#980,.T.);
#982=ADVANCED_FACE('F416',(#970,#981),#967,.F.);
#983=CARTESIAN_POINT('',(0.,0.,35.0080113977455));
#984=DIRECTION('',(0.,0.,1.));
#985=DIRECTION('',(-1.,0.,0.));
#986=AXIS2_PLACEMENT_3D('',#983,#984,#985);
#987=CYLINDRICAL_SURFACE('',#986,7.);
#988=CARTESIAN_POINT('',(0.,0.,0.199999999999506));
#989=DIRECTION('',(0.,0.,1.));
#990=DIRECTION('',(-1.,0.,0.));
#991=AXIS2_PLACEMENT_3D('',#988,#989,#990);
#992=CIRCLE('',#991,7.);
#993=CARTESIAN_POINT('',(-7.,0.,0.199999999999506));
#994=VERTEX_POINT('',#993);
#995=EDGE_CURVE('E866',#994,#994,#992,.T.);
#996=ORIENTED_EDGE('',*,*,#995,.T.);
#997=EDGE_LOOP('',(#996));
#998=FACE_BOUND('',#997,.T.);
#999=ORIENTED_EDGE('',*,*,#978,.F.);
#1000=EDGE_LOOP('',(#999));
#1001=FACE_BOUND('',#1000,.T.);
#1002=ADVANCED_FACE('F412',(#998,#1001),#987,.T.);
#1003=CARTESIAN_POINT('',(0.,0.,-4.9960036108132E-13));
#1004=DIRECTION('',(0.,0.,1.));
#1005=DIRECTION('',(-1.,0.,0.));
#1006=AXIS2_PLACEMENT_3D('',#1003,#1004,#1005);
#1007=CONICAL_SURFACE('',#1006,6.8,0.785398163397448);
#1008=ORIENTED_EDGE('',*,*,#995,.F.);
#1009=EDGE_LOOP('',(#1008));
#1010=FACE_BOUND('',#1009,.T.);
#1011=CARTESIAN_POINT('',(0.,0.,-4.9960036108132E-13));
#1012=DIRECTION('',(0.,0.,1.));
#1013=DIRECTION('',(-1.,0.,0.));
#1014=AXIS2_PLACEMENT_3D('',#1011,#1012,#1013);
#1015=CIRCLE('',#1014,6.8);
#1016=CARTESIAN_POINT('',(-6.8,0.,-4.9960036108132E-13));
#1017=VERTEX_POINT('',#1016);
#1018=EDGE_CURVE('E864',#1017,#1017,#1015,.T.);
#1019=ORIENTED_EDGE('',*,*,#1018,.T.);
#1020=EDGE_LOOP('',(#1019));
#1021=FACE_BOUND('',#1020,.T.);
#1022=ADVANCED_FACE('F408',(#1010,#1021),#1007,.T.);
#1023=CARTESIAN_POINT('',(0.,0.,0.));
#1024=DIRECTION('',(0.,0.,1.));
#1025=DIRECTION('',(-1.,0.,0.));
#1026=AXIS2_PLACEMENT_3D('',#1023,#1024,#1025);
#1027=PLANE('',#1026);
#1028=CARTESIAN_POINT('',(0.,0.,0.));
#1029=DIRECTION('',(0.,0.,-1.));
#1030=DIRECTION('',(1.,0.,0.));
#1031=AXIS2_PLACEMENT_3D('',#1028,#1029,#1030);
#1032=CIRCLE('',#1031,4.);
#1033=CARTESIAN_POINT('',(4.,0.,0.));
#1034=VERTEX_POINT('',#1033);
#1035=EDGE_CURVE('E856',#1034,#1034,#1032,.T.);
#1036=ORIENTED_EDGE('',*,*,#1035,.F.);
#1037=EDGE_LOOP('',(#1036));
#1038=FACE_BOUND('',#1037,.T.);
#1039=ORIENTED_EDGE('',*,*,#1018,.F.);
#1040=EDGE_LOOP('',(#1039));
#1041=FACE_BOUND('',#1040,.T.);
#1042=ADVANCED_FACE('F402',(#1038,#1041),#1027,.F.);
#1043=CARTESIAN_POINT('',(0.,0.,23.160797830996));
#1044=DIRECTION('',(0.,0.,1.));
#1045=DIRECTION('',(-1.,0.,0.));
#1046=AXIS2_PLACEMENT_3D('',#1043,#1044,#1045);
#1047=CYLINDRICAL_SURFACE('',#1046,10.);
#1048=CARTESIAN_POINT('',(0.,0.,23.160797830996));
#1049=DIRECTION('',(0.,0.,1.));
#1050=DIRECTION('',(-1.,0.,0.));
#1051=AXIS2_PLACEMENT_3D('',#1048,#1049,#1050);
#1052=CIRCLE('',#1051,10.);
#1053=CARTESIAN_POINT('',(-10.,0.,23.160797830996));
#1054=VERTEX_POINT('',#1053);
#1055=EDGE_CURVE('E203',#1054,#1054,#1052,.T.);
#1056=ORIENTED_EDGE('',*,*,#1055,.F.);
#1057=EDGE_LOOP('',(#1056));
#1058=FACE_BOUND('',#1057,.T.);
#1059=ORIENTED_EDGE('',*,*,#224,.T.);
#1060=EDGE_LOOP('',(#1059));
#1061=FACE_BOUND('',#1060,.T.);
#1062=ADVANCED_FACE('F233',(#1058,#1061),#1047,.F.);
#1063=CARTESIAN_POINT('',(0.,0.,23.160797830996));
#1064=DIRECTION('',(0.,0.,1.));
#1065=DIRECTION('',(-1.,0.,0.));
#1066=AXIS2_PLACEMENT_3D('',#1063,#1064,#1065);
#1067=PLANE('',#1066);
#1068=ORIENTED_EDGE('',*,*,#1055,.T.);
#1069=EDGE_LOOP('',(#1068));
#1070=FACE_BOUND('',#1069,.T.);
#1071=ADVANCED_FACE('F232',(#1070),#1067,.T.);
#1072=CARTESIAN_POINT('',(-16.5,28.5788383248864,-4.9960036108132E-13));
#1073=DIRECTION('',(0.,0.,1.));
#1074=DIRECTION('',(-1.,0.,0.));
#1075=AXIS2_PLACEMENT_3D('',#1072,#1073,#1074);
#1076=CYLINDRICAL_SURFACE('',#1075,16.);
#1077=DIRECTION('',(0.,0.,1.));
#1078=VECTOR('',#1077,1.);
#1079=CARTESIAN_POINT('',(-3.96883886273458,18.6304715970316,-4.9960036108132E-13));
#1080=LINE('',#1079,#1078);
#1081=EDGE_CURVE('E29',#919,#270,#1080,.T.);
#1082=ORIENTED_EDGE('',*,*,#1081,.F.);
#1083=ORIENTED_EDGE('',*,*,#920,.T.);
#1084=DIRECTION('',(0.,0.,1.));
#1085=VECTOR('',#1084,1.);
#1086=CARTESIAN_POINT('',(-14.1500422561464,12.7523510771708,-4.9960036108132E-13));
#1087=LINE('',#1086,#1085);
#1088=EDGE_CURVE('E177',#910,#321,#1087,.T.);
#1089=ORIENTED_EDGE('',*,*,#1088,.T.);
#1090=ORIENTED_EDGE('',*,*,#322,.F.);
#1091=EDGE_LOOP('',(#1082,#1083,#1089,#1090));
#1092=FACE_BOUND('',#1091,.T.);
#1093=ADVANCED_FACE('F175',(#1092),#1076,.F.);
#1094=CARTESIAN_POINT('',(-13.6359889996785,9.290306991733,-4.9960036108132E-13));
#1095=DIRECTION('',(0.,0.,1.));
#1096=DIRECTION('',(-1.,0.,0.));
#1097=AXIS2_PLACEMENT_3D('',#1094,#1095,#1096);
#1098=CYLINDRICAL_SURFACE('',#1097,3.5);
#1099=ORIENTED_EDGE('',*,*,#337,.T.);
#1100=ORIENTED_EDGE('',*,*,#1088,.F.);
#1101=ORIENTED_EDGE('',*,*,#911,.F.);
#1102=ORIENTED_EDGE('',*,*,#191,.T.);
#1103=EDGE_LOOP('',(#1099,#1100,#1101,#1102));
#1104=FACE_BOUND('',#1103,.T.);
#1105=ADVANCED_FACE('F226',(#1104),#1098,.T.);
#1106=CARTESIAN_POINT('',(-1.22764736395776,16.4542663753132,-4.9960036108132E-13));
#1107=DIRECTION('',(0.,0.,1.));
#1108=DIRECTION('',(-1.,0.,0.));
#1109=AXIS2_PLACEMENT_3D('',#1106,#1107,#1108);
#1110=CYLINDRICAL_SURFACE('',#1109,3.5);
#1111=ORIENTED_EDGE('',*,*,#271,.T.);
#1112=ORIENTED_EDGE('',*,*,#41,.F.);
#1113=ORIENTED_EDGE('',*,*,#927,.F.);
#1114=ORIENTED_EDGE('',*,*,#1081,.T.);
#1115=EDGE_LOOP('',(#1111,#1112,#1113,#1114));
#1116=FACE_BOUND('',#1115,.T.);
#1117=ADVANCED_FACE('F185',(#1116),#1110,.T.);
#1118=CARTESIAN_POINT('',(-14.8636363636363,7.16395938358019,-4.9960036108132E-13));
#1119=DIRECTION('',(0.,0.,1.));
#1120=DIRECTION('',(-1.,0.,0.));
#1121=AXIS2_PLACEMENT_3D('',#1118,#1119,#1120);
#1122=CYLINDRICAL_SURFACE('',#1121,3.5);
#1123=ORIENTED_EDGE('',*,*,#359,.T.);
#1124=ORIENTED_EDGE('',*,*,#181,.F.);
#1125=ORIENTED_EDGE('',*,*,#901,.F.);
#1126=DIRECTION('',(0.,0.,1.));
#1127=VECTOR('',#1126,1.);
#1128=CARTESIAN_POINT('',(-18.118881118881,5.87812051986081,-4.9960036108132E-13));
#1129=LINE('',#1128,#1127);
#1130=EDGE_CURVE('E586',#893,#358,#1129,.T.);
#1131=ORIENTED_EDGE('',*,*,#1130,.T.);
#1132=EDGE_LOOP('',(#1123,#1124,#1125,#1131));
#1133=FACE_BOUND('',#1132,.T.);
#1134=ADVANCED_FACE('F225',(#1133),#1122,.T.);
#1135=CARTESIAN_POINT('',(-33.,0.,-4.9960036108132E-13));
#1136=DIRECTION('',(0.,0.,1.));
#1137=DIRECTION('',(-1.,0.,0.));
#1138=AXIS2_PLACEMENT_3D('',#1135,#1136,#1137);
#1139=CYLINDRICAL_SURFACE('',#1138,16.);
#1140=ORIENTED_EDGE('',*,*,#1130,.F.);
#1141=ORIENTED_EDGE('',*,*,#894,.T.);
#1142=DIRECTION('',(0.,0.,1.));
#1143=VECTOR('',#1142,1.);
#1144=CARTESIAN_POINT('',(-18.118881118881,-5.87812051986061,-4.9960036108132E-13));
#1145=LINE('',#1144,#1143);
#1146=EDGE_CURVE('E589',#884,#409,#1145,.T.);
#1147=ORIENTED_EDGE('',*,*,#1146,.T.);
#1148=ORIENTED_EDGE('',*,*,#410,.F.);
#1149=EDGE_LOOP('',(#1140,#1141,#1147,#1148));
#1150=FACE_BOUND('',#1149,.T.);
#1151=ADVANCED_FACE('F263',(#1150),#1139,.F.);
#1152=CARTESIAN_POINT('',(-14.8636363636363,-7.16395938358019,-4.9960036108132E-13));
#1153=DIRECTION('',(0.,0.,1.));
#1154=DIRECTION('',(-1.,0.,0.));
#1155=AXIS2_PLACEMENT_3D('',#1152,#1153,#1154);
#1156=CYLINDRICAL_SURFACE('',#1155,3.5);
#1157=ORIENTED_EDGE('',*,*,#425,.T.);
#1158=ORIENTED_EDGE('',*,*,#1146,.F.);
#1159=ORIENTED_EDGE('',*,*,#885,.F.);
#1160=ORIENTED_EDGE('',*,*,#164,.T.);
#1161=EDGE_LOOP('',(#1157,#1158,#1159,#1160));
#1162=FACE_BOUND('',#1161,.T.);
#1163=ADVANCED_FACE('F267',(#1162),#1156,.T.);
#1164=CARTESIAN_POINT('',(-13.6359889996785,-9.290306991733,-4.9960036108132E-13));
#1165=DIRECTION('',(0.,0.,1.));
#1166=DIRECTION('',(-1.,0.,0.));
#1167=AXIS2_PLACEMENT_3D('',#1164,#1165,#1166);
#1168=CYLINDRICAL_SURFACE('',#1167,3.5);
#1169=ORIENTED_EDGE('',*,*,#447,.T.);
#1170=ORIENTED_EDGE('',*,*,#154,.F.);
#1171=ORIENTED_EDGE('',*,*,#875,.F.);
#1172=DIRECTION('',(0.,0.,1.));
#1173=VECTOR('',#1172,1.);
#1174=CARTESIAN_POINT('',(-14.1500422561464,-12.752351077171,-4.9960036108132E-13));
#1175=LINE('',#1174,#1173);
#1176=EDGE_CURVE('E596',#867,#446,#1175,.T.);
#1177=ORIENTED_EDGE('',*,*,#1176,.T.);
#1178=EDGE_LOOP('',(#1169,#1170,#1171,#1177));
#1179=FACE_BOUND('',#1178,.T.);
#1180=ADVANCED_FACE('F272',(#1179),#1168,.T.);
#1181=CARTESIAN_POINT('',(-16.5,-28.5788383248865,-4.9960036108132E-13));
#1182=DIRECTION('',(0.,0.,1.));
#1183=DIRECTION('',(-1.,0.,0.));
#1184=AXIS2_PLACEMENT_3D('',#1181,#1182,#1183);
#1185=CYLINDRICAL_SURFACE('',#1184,16.);
#1186=ORIENTED_EDGE('',*,*,#1176,.F.);
#1187=ORIENTED_EDGE('',*,*,#868,.T.);
#1188=DIRECTION('',(0.,0.,1.));
#1189=VECTOR('',#1188,1.);
#1190=CARTESIAN_POINT('',(-3.96883886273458,-18.6304715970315,-4.9960036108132E-13));
#1191=LINE('',#1190,#1189);
#1192=EDGE_CURVE('E599',#858,#497,#1191,.T.);
#1193=ORIENTED_EDGE('',*,*,#1192,.T.);
#1194=ORIENTED_EDGE('',*,*,#498,.F.);
#1195=EDGE_LOOP('',(#1186,#1187,#1193,#1194));
#1196=FACE_BOUND('',#1195,.T.);
#1197=ADVANCED_FACE('F302',(#1196),#1185,.F.);
#1198=CARTESIAN_POINT('',(-1.22764736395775,-16.4542663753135,-4.9960036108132E-13));
#1199=DIRECTION('',(0.,0.,1.));
#1200=DIRECTION('',(-1.,0.,0.));
#1201=AXIS2_PLACEMENT_3D('',#1198,#1199,#1200);
#1202=CYLINDRICAL_SURFACE('',#1201,3.5);
#1203=ORIENTED_EDGE('',*,*,#513,.T.);
#1204=ORIENTED_EDGE('',*,*,#1192,.F.);
#1205=ORIENTED_EDGE('',*,*,#859,.F.);
#1206=ORIENTED_EDGE('',*,*,#137,.T.);
#1207=EDGE_LOOP('',(#1203,#1204,#1205,#1206));
#1208=FACE_BOUND('',#1207,.T.);
#1209=ADVANCED_FACE('F305',(#1208),#1202,.T.);
#1210=CARTESIAN_POINT('',(1.22764736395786,-16.4542663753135,-4.9960036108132E-13));
#1211=DIRECTION('',(0.,0.,1.));
#1212=DIRECTION('',(-1.,0.,0.));
#1213=AXIS2_PLACEMENT_3D('',#1210,#1211,#1212);
#1214=CYLINDRICAL_SURFACE('',#1213,3.5);
#1215=ORIENTED_EDGE('',*,*,#535,.T.);
#1216=ORIENTED_EDGE('',*,*,#127,.F.);
#1217=ORIENTED_EDGE('',*,*,#849,.F.);
#1218=DIRECTION('',(0.,0.,1.));
#1219=VECTOR('',#1218,1.);
#1220=CARTESIAN_POINT('',(3.96883886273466,-18.6304715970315,-4.9960036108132E-13));
#1221=LINE('',#1220,#1219);
#1222=EDGE_CURVE('E606',#841,#534,#1221,.T.);
#1223=ORIENTED_EDGE('',*,*,#1222,.T.);
#1224=EDGE_LOOP('',(#1215,#1216,#1217,#1223));
#1225=FACE_BOUND('',#1224,.T.);
#1226=ADVANCED_FACE('F310',(#1225),#1214,.T.);
#1227=CARTESIAN_POINT('',(16.5,-28.5788383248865,-4.9960036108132E-13));
#1228=DIRECTION('',(0.,0.,1.));
#1229=DIRECTION('',(-1.,0.,0.));
#1230=AXIS2_PLACEMENT_3D('',#1227,#1228,#1229);
#1231=CYLINDRICAL_SURFACE('',#1230,16.);
#1232=ORIENTED_EDGE('',*,*,#1222,.F.);
#1233=ORIENTED_EDGE('',*,*,#842,.T.);
#1234=DIRECTION('',(0.,0.,1.));
#1235=VECTOR('',#1234,1.);
#1236=CARTESIAN_POINT('',(14.1500422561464,-12.752351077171,-4.9960036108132E-13));
#1237=LINE('',#1236,#1235);
#1238=EDGE_CURVE('E609',#832,#585,#1237,.T.);
#1239=ORIENTED_EDGE('',*,*,#1238,.T.);
#1240=ORIENTED_EDGE('',*,*,#586,.F.);
#1241=EDGE_LOOP('',(#1232,#1233,#1239,#1240));
#1242=FACE_BOUND('',#1241,.T.);
#1243=ADVANCED_FACE('F315',(#1242),#1231,.F.);
#1244=CARTESIAN_POINT('',(13.6359889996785,-9.290306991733,-4.9960036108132E-13));
#1245=DIRECTION('',(0.,0.,1.));
#1246=DIRECTION('',(-1.,0.,0.));
#1247=AXIS2_PLACEMENT_3D('',#1244,#1245,#1246);
#1248=CYLINDRICAL_SURFACE('',#1247,3.5);
#1249=ORIENTED_EDGE('',*,*,#601,.T.);
#1250=ORIENTED_EDGE('',*,*,#1238,.F.);
#1251=ORIENTED_EDGE('',*,*,#833,.F.);
#1252=ORIENTED_EDGE('',*,*,#110,.T.);
#1253=EDGE_LOOP('',(#1249,#1250,#1251,#1252));
#1254=FACE_BOUND('',#1253,.T.);
#1255=ADVANCED_FACE('F345',(#1254),#1248,.T.);
#1256=CARTESIAN_POINT('',(14.8636363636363,-7.16395938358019,-4.9960036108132E-13));
#1257=DIRECTION('',(0.,0.,1.));
#1258=DIRECTION('',(-1.,0.,0.));
#1259=AXIS2_PLACEMENT_3D('',#1256,#1257,#1258);
#1260=CYLINDRICAL_SURFACE('',#1259,3.5);
#1261=ORIENTED_EDGE('',*,*,#623,.T.);
#1262=ORIENTED_EDGE('',*,*,#100,.F.);
#1263=ORIENTED_EDGE('',*,*,#823,.F.);
#1264=DIRECTION('',(0.,0.,1.));
#1265=VECTOR('',#1264,1.);
#1266=CARTESIAN_POINT('',(18.118881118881,-5.87812051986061,-4.9960036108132E-13));
#1267=LINE('',#1266,#1265);
#1268=EDGE_CURVE('E566',#815,#622,#1267,.T.);
#1269=ORIENTED_EDGE('',*,*,#1268,.T.);
#1270=EDGE_LOOP('',(#1261,#1262,#1263,#1269));
#1271=FACE_BOUND('',#1270,.T.);
#1272=ADVANCED_FACE('F348',(#1271),#1260,.T.);
#1273=CARTESIAN_POINT('',(33.,0.,-4.9960036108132E-13));
#1274=DIRECTION('',(0.,0.,1.));
#1275=DIRECTION('',(-1.,0.,0.));
#1276=AXIS2_PLACEMENT_3D('',#1273,#1274,#1275);
#1277=CYLINDRICAL_SURFACE('',#1276,16.);
#1278=ORIENTED_EDGE('',*,*,#1268,.F.);
#1279=ORIENTED_EDGE('',*,*,#816,.T.);
#1280=DIRECTION('',(0.,0.,1.));
#1281=VECTOR('',#1280,1.);
#1282=CARTESIAN_POINT('',(18.118881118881,5.87812051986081,-4.9960036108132E-13));
#1283=LINE('',#1282,#1281);
#1284=EDGE_CURVE('E563',#806,#673,#1283,.T.);
#1285=ORIENTED_EDGE('',*,*,#1284,.T.);
#1286=ORIENTED_EDGE('',*,*,#674,.F.);
#1287=EDGE_LOOP('',(#1278,#1279,#1285,#1286));
#1288=FACE_BOUND('',#1287,.T.);
#1289=ADVANCED_FACE('F353',(#1288),#1277,.F.);
#1290=CARTESIAN_POINT('',(14.8636363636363,7.16395938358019,-4.9960036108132E-13));
#1291=DIRECTION('',(0.,0.,1.));
#1292=DIRECTION('',(-1.,0.,0.));
#1293=AXIS2_PLACEMENT_3D('',#1290,#1291,#1292);
#1294=CYLINDRICAL_SURFACE('',#1293,3.5);
#1295=ORIENTED_EDGE('',*,*,#689,.T.);
#1296=ORIENTED_EDGE('',*,*,#1284,.F.);
#1297=ORIENTED_EDGE('',*,*,#807,.F.);
#1298=ORIENTED_EDGE('',*,*,#83,.T.);
#1299=EDGE_LOOP('',(#1295,#1296,#1297,#1298));
#1300=FACE_BOUND('',#1299,.T.);
#1301=ADVANCED_FACE('F358',(#1300),#1294,.T.);
#1302=CARTESIAN_POINT('',(1.22764736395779,16.4542663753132,-4.9960036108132E-13));
#1303=DIRECTION('',(0.,0.,1.));
#1304=DIRECTION('',(-1.,0.,0.));
#1305=AXIS2_PLACEMENT_3D('',#1302,#1303,#1304);
#1306=CYLINDRICAL_SURFACE('',#1305,3.5);
#1307=ORIENTED_EDGE('',*,*,#249,.T.);
#1308=DIRECTION('',(0.,0.,1.));
#1309=VECTOR('',#1308,1.);
#1310=CARTESIAN_POINT('',(3.96883886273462,18.6304715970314,-4.9960036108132E-13));
#1311=LINE('',#1310,#1309);
#1312=EDGE_CURVE('E576',#780,#248,#1311,.T.);
#1313=ORIENTED_EDGE('',*,*,#1312,.F.);
#1314=ORIENTED_EDGE('',*,*,#781,.F.);
#1315=ORIENTED_EDGE('',*,*,#56,.T.);
#1316=EDGE_LOOP('',(#1307,#1313,#1314,#1315));
#1317=FACE_BOUND('',#1316,.T.);
#1318=ADVANCED_FACE('F393',(#1317),#1306,.T.);
#1319=CARTESIAN_POINT('',(16.5,28.5788383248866,-4.9960036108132E-13));
#1320=DIRECTION('',(0.,0.,1.));
#1321=DIRECTION('',(-1.,0.,0.));
#1322=AXIS2_PLACEMENT_3D('',#1319,#1320,#1321);
#1323=CYLINDRICAL_SURFACE('',#1322,16.);
#1324=DIRECTION('',(0.,0.,1.));
#1325=VECTOR('',#1324,1.);
#1326=CARTESIAN_POINT('',(14.1500422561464,12.752351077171,-4.9960036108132E-13));
#1327=LINE('',#1326,#1325);
#1328=EDGE_CURVE('E574',#789,#710,#1327,.T.);
#1329=ORIENTED_EDGE('',*,*,#1328,.F.);
#1330=ORIENTED_EDGE('',*,*,#790,.T.);
#1331=ORIENTED_EDGE('',*,*,#1312,.T.);
#1332=ORIENTED_EDGE('',*,*,#760,.F.);
#1333=EDGE_LOOP('',(#1329,#1330,#1331,#1332));
#1334=FACE_BOUND('',#1333,.T.);
#1335=ADVANCED_FACE('F388',(#1334),#1323,.F.);
#1336=CARTESIAN_POINT('',(13.6359889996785,9.290306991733,-4.9960036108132E-13));
#1337=DIRECTION('',(0.,0.,1.));
#1338=DIRECTION('',(-1.,0.,0.));
#1339=AXIS2_PLACEMENT_3D('',#1336,#1337,#1338);
#1340=CYLINDRICAL_SURFACE('',#1339,3.5);
#1341=ORIENTED_EDGE('',*,*,#711,.T.);
#1342=ORIENTED_EDGE('',*,*,#73,.F.);
#1343=ORIENTED_EDGE('',*,*,#797,.F.);
#1344=ORIENTED_EDGE('',*,*,#1328,.T.);
#1345=EDGE_LOOP('',(#1341,#1342,#1343,#1344));
#1346=FACE_BOUND('',#1345,.T.);
#1347=ADVANCED_FACE('F385',(#1346),#1340,.T.);
#1348=CARTESIAN_POINT('',(0.,0.,16.));
#1349=DIRECTION('',(0.,0.,-1.));
#1350=DIRECTION('',(1.,0.,0.));
#1351=AXIS2_PLACEMENT_3D('',#1348,#1349,#1350);
#1352=CYLINDRICAL_SURFACE('',#1351,4.);
#1353=CARTESIAN_POINT('',(0.,0.,16.));
#1354=DIRECTION('',(0.,0.,-1.));
#1355=DIRECTION('',(1.,0.,0.));
#1356=AXIS2_PLACEMENT_3D('',#1353,#1354,#1355);
#1357=CIRCLE('',#1356,4.);
#1358=CARTESIAN_POINT('',(4.,0.,16.));
#1359=VERTEX_POINT('',#1358);
#1360=EDGE_CURVE('E191',#1359,#1359,#1357,.T.);
#1361=ORIENTED_EDGE('',*,*,#1360,.F.);
#1362=EDGE_LOOP('',(#1361));
#1363=FACE_BOUND('',#1362,.T.);
#1364=ORIENTED_EDGE('',*,*,#1035,.T.);
#1365=EDGE_LOOP('',(#1364));
#1366=FACE_BOUND('',#1365,.T.);
#1367=ADVANCED_FACE('F227',(#1363,#1366),#1352,.F.);
#1368=CARTESIAN_POINT('',(0.,0.,16.));
#1369=DIRECTION('',(0.,0.,-1.));
#1370=DIRECTION('',(1.,0.,0.));
#1371=AXIS2_PLACEMENT_3D('',#1368,#1369,#1370);
#1372=PLANE('',#1371);
#1373=ORIENTED_EDGE('',*,*,#1360,.T.);
#1374=EDGE_LOOP('',(#1373));
#1375=FACE_BOUND('',#1374,.T.);
#1376=ADVANCED_FACE('F390',(#1375),#1372,.T.);
#1377=CLOSED_SHELL('',(#60,#87,#114,#141,#168,#195,#228,#767,#942,#962,#982,#1002,#1022,#1042,
#1062,#1071,#1093,#1105,#1117,#1134,#1151,#1163,#1180,#1197,#1209,#1226,#1243,#1255,#1272,#1289,
#1301,#1318,#1335,#1347,#1367,#1376));
#1378=MANIFOLD_SOLID_BREP('B1',#1377);
#1379=ADVANCED_BREP_SHAPE_REPRESENTATION('',(#18,#1378),#14);
#1380=SHAPE_DEFINITION_REPRESENTATION(#9,#1379);
ENDSEC;
END-ISO-10303-21;
